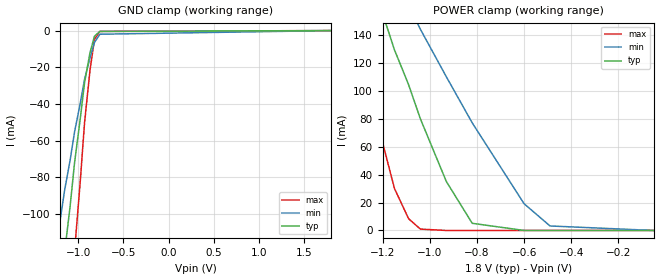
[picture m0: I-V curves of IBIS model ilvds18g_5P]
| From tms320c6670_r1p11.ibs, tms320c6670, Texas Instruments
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|   Model Cell ilvds18g_5P
|ilvds18g_5P
[Model]   ilvds18g_5P
Model_type   Input
Polarity   Non-Inverting
Vinl =  1.15
Vinh =  1.25
C_comp   0.840487p   0.785062p   0.905604p
[Model Spec]
Vinl   1.15   1.15   1.15
Vinh   1.25   1.25   1.25
[Temperature Range]   25   105   -40
[Voltage Range]   1.8   1.71   1.89
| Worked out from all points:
|   GND clamp passes 1 mA (typ) near -0.77 V on its own axis
|   POWER clamp passes 1 mA (typ) near -0.76 V on its own axis
[GND_clamp]
|   voltage   I(typ)   I(min)   I(max)
-1.8V     -438.9mA   -295.8mA   -676.9mA
-1.25V    -172mA     -120.3mA   -273.9mA
-1.2V     -146.2mA   -103.5mA   -234.6mA
-1.15V    -120.8mA   -86.95mA   -195.8mA
-1.09V    -95.96mA   -70.79mA   -157.5mA
-1.04V    -71.89mA   -55.15mA   -120mA
-980mV    -49.09mA   -40.28mA   -83.91mA
-930mV    -28.48mA   -26.62mA   -50.27mA
-870mV    -12.11mA   -14.93mA   -21.77mA
-820mV    -3.023mA   -6.438mA   -4.634mA
-760mV    -470.2uA   -1.993mA   -441.6uA
1.8V      23.4pA     3.455nA    19.89pA
[POWER_clamp]
|   voltage   I(typ)   I(min)   I(max)
-1.8V     448.2mA    392.9mA    487.2mA
-1.64V    367.1mA    338.8mA    366.4mA
-1.31V    207mA      231.6mA    132.1mA
-1.25V    180.9mA    213.9mA    95.42mA
-1.15V    129.4mA    178.8mA    30.1mA
-1.09V    104.4mA    161.4mA    8.438mA
-1.04V    79.98mA    144.1mA    975.6uA
-930mV    35.12mA    110.1mA    5.229uA
-820mV    5.137mA    77.05mA    25.89nA
-600mV    1.898uA    19.14mA    36.12pA
-490mV    29.59nA    3.23mA     32.66pA
-50mV     24.82pA    16.42nA    21.31pA
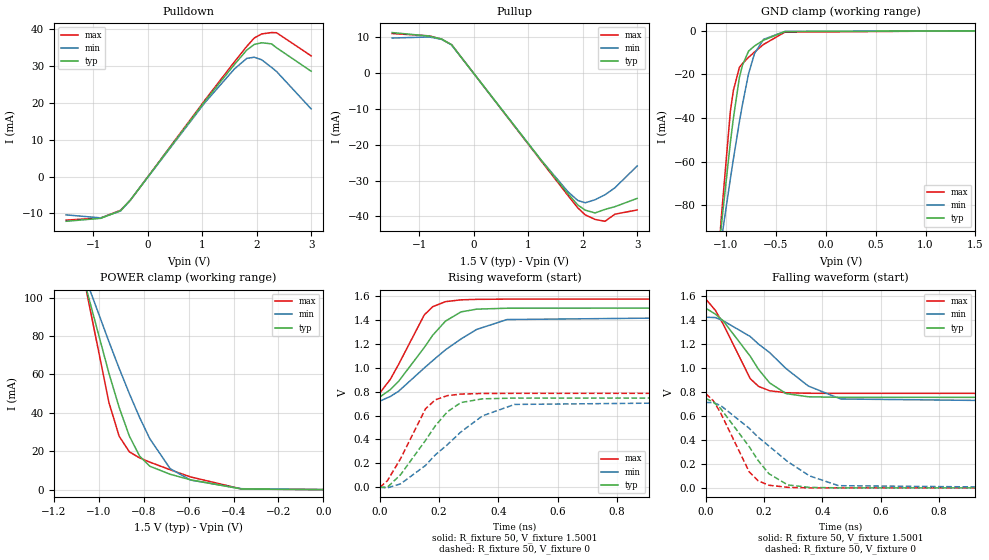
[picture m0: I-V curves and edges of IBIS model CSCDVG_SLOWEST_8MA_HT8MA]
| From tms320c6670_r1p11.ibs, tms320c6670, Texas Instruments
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|   Model Cell CSCDVG_SLOWEST_8MA_HT8MA
|SLOWEST_8MA
[Model]   CSCDVG_SLOWEST_8MA_HT8MA
Model_type   I/O
Polarity   Non-Inverting
Enable   Active-Low
Cref =  4.0000pF
Rref =  100.0000M
Vref =  0V
Vmeas =  0.75
C_comp   1.5249p   1.4275p   1.6205p
|[mode_tieoffpin] SR0=1  SR1=1 I0=0 I1=0 I2=1
[Model Spec]
Vinl   0.6125   0.6125   0.6125
Vinh   0.9625   0.9625   0.9625
D_overshoot_high 1.95 1.95 1.95
D_overshoot_low -0.3 -0.3 -0.3
D_overshoot_time 1E-9 1E-9 1E-9
S_overshoot_high 1.575 1.575 1.575
S_overshoot_low 0 0 0
[Receiver Thresholds]
Reference_supply Pullup_ref
Threshold_sensitivity= 0.5
Tslew_ac= 5nS
Vinh_ac= +175mV
Vinh_dc= +100mV
Vinl_ac= -175mV
Vinl_dc= -100mV
Vth = 0.75
Vth_max= 0.79
Vth_min= 0.71
[Pullup Reference] 1.5001   1.425   1.575
[Add Submodel]
|Submodel_name Mode
CSCDVG_HT_TH_8MA Non-Driving
[Temperature Range]   25   105   -40
[Voltage Range]   1.5   1.425   1.575
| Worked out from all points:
|   slope of the pulldown table from 0 to 0.225 V, typ, clamps not added: 50.1 ohm
|   slope of the pullup table from 0 to 0.225 V, typ, clamps not added: 50.1 ohm
|   GND clamp passes 1 mA (typ) near -0.47 V on its own axis
|   POWER clamp passes 1 mA (typ) near -0.42 V on its own axis
|   rising waveform, R_fixture 50, V_fixture 1.5001: 20-80 % time 136ps typ, 208ps min, 98ps max; typ from 0.756 V to 1.5 V
|   rising waveform, R_fixture 50, V_fixture 0: 20-80 % time 132ps typ, 191ps min, 95.4ps max; typ from 0 V to 0.747 V
|   falling waveform, R_fixture 50, V_fixture 1.5001: 20-80 % time 135ps typ, 202ps min, 94.9ps max; typ from 1.5 V to 0.755 V
|   falling waveform, R_fixture 50, V_fixture 0: 20-80 % time 132ps typ, 207ps min, 92.7ps max; typ from 0.746 V to 0 V
[POWER_clamp]
|   voltage   I(typ)   I(min)   I(max)
-1.5V     321.7mA    260.6mA    415.9mA
-1.076V   114.2mA    115.8mA    116.9mA
-1.061V   107.2mA    110.9mA    107.1mA
-954.6mV  60.59mA    77.06mA    45.35mA
-909.2mV  42.85mA    63.21mA    27.81mA
-863.7mV  27.9mA     49.99mA    19.69mA
-818.2mV  17.49mA    37.63mA    16.52mA
-772.8mV  12.19mA    26.53mA    14.33mA
-681.9mV  7.985mA    10.89mA    10.33mA
-590.9mV  5.094mA    4.955mA    6.6mA
-363.7mV  298.5uA    465.2uA    297.6uA
0V        1.518nA    24.08nA    367.8pA
[Pulldown]
|   voltage   I(typ)   I(min)   I(max)
-1.5V     -12.15mA   -10.4mA    -11.83mA
-863.7mV  -11.34mA   -11.22mA   -11.25mA
-500mV    -9.267mA   -9.352mA   -9.148mA
-318.2mV  -6.354mA   -6.371mA   -6.385mA
1.046V    20.42mA    20.05mA    20.72mA
1.591V    30.47mA    29.26mA    31.18mA
1.818V    34.39mA    32.13mA    35.4mA
1.955V    35.92mA    32.45mA    37.67mA
2.091V    36.38mA    31.76mA    38.77mA
2.273V    36.08mA    29.69mA    39.15mA
2.364V    35.03mA    28.59mA    39.11mA
3V        28.64mA    18.41mA    32.82mA
[Pullup]
|   voltage   I(typ)   I(min)   I(max)
-1.5V     11.21mA    9.69mA     10.94mA
-818.2mV  10.23mA    9.978mA    10.29mA
-590.9mV  9.401mA    9.328mA    9.374mA
-409.1mV  7.828mA    7.781mA    7.859mA
1.227V    -24.14mA   -24.11mA   -24.35mA
1.727V    -33.63mA   -33.09mA   -34.13mA
1.909V    -36.81mA   -35.55mA   -37.6mA
2.046V    -38.25mA   -36.2mA    -39.57mA
2.227V    -39.04mA   -35.36mA   -40.83mA
2.409V    -38.05mA   -33.98mA   -41.36mA
2.591V    -37.29mA   -32.03mA   -39.38mA
3V        -34.98mA   -25.95mA   -38.2mA
[GND_clamp]
|   voltage   I(typ)   I(min)   I(max)
-1.5V     -310.1mA   -250.5mA   -402.5mA
-1.076V   -103.6mA   -106.2mA   -105.2mA
-1.046V   -89.81mA   -96.36mA   -86.02mA
-954.6mV  -51.22mA   -67.87mA   -36.88mA
-924.3mV  -40.08mA   -58.86mA   -27.29mA
-863.7mV  -21.24mA   -41.56mA   -16.73mA
-833.4mV  -15.8mA    -33.75mA   -15.03mA
-772.8mV  -9.345mA   -19.75mA   -12.19mA
-712.2mV  -6.928mA   -10.35mA   -9.704mA
-621.3mV  -4.261mA   -3.896mA   -6.225mA
-409.1mV  -337.1uA   -289.1uA   -618.9uA
1.5V      1.518nA    257.2nA    299pA
[Ramp]
| variable   typ   min   max
dV/dt_f   0.596016/0.19469535n   0.56432/0.3101823n   0.629272/0.14102085n
dV/dt_r  0.6013584/0.19239092n 0.57508648/0.29752883n 0.63081544/0.1406002n
R_load = 50
[Rising Waveform]
R_fixture = 50
V_fixture = 1.5001
V_fixture_min = 1.425
V_fixture_max = 1.575
|   time   V(typ)   V(min)   V(max)
0s        755.9mV    721.6mV    789.3mV
35.49ps   817.7mV    760.2mV    904.4mV
62.87ps   885.6mV    803mV      1.027V
149.8ps   1.17V      998.8mV    1.443V
178.6ps   1.274V     1.061V     1.512V
221.3ps   1.391V     1.151V     1.554V
273.4ps   1.468V     1.241V     1.569V
326.2ps   1.491V     1.321V     1.573V
428.6ps   1.499V     1.404V     1.575V
1.283ns   1.5V       1.425V     1.575V
[Rising Waveform]
R_fixture = 50
V_fixture = 0
V_fixture_min = 0
V_fixture_max = 0
|   time   V(typ)   V(min)   V(max)
0s        0V         0V         0V
25.42ps   0V         -5.021mV   54.37mV
69.9ps    105.4mV    28.32mV    239.7mV
153.8ps   392.2mV    182.2mV    656.3mV
186.7ps   513.3mV    270.6mV    731.7mV
227.1ps   630.7mV    355.1mV    766.8mV
273.1ps   709mV      462.7mV    780.1mV
345.9ps   740.4mV    597.8mV    785.2mV
454.4ps   746.6mV    693.4mV    786.1mV
1.291ns   747.3mV    712.8mV    786.3mV
[Falling Waveform]
R_fixture = 50
V_fixture = 1.5001
V_fixture_min = 1.425
V_fixture_max = 1.575
|   time   V(typ)   V(min)   V(max)
0s        1.499V     1.424V     1.575V
33.01ps   1.449V     1.421V     1.48V
59.02ps   1.395V     1.395V     1.368V
152.3ps   1.098V     1.263V     910.9mV
180.5ps   989.3mV    1.2V       847.3mV
218.6ps   876.3mV    1.129V     810.4mV
275.3ps   786.6mV    995.1mV    793.7mV
351.6ps   760.1mV    849.6mV    789.3mV
462.4ps   755.6mV    741.7mV    788.7mV
1.283ns   755.2mV    720.6mV    788.5mV
[Falling Waveform]
R_fixture = 50
V_fixture = 0
V_fixture_min = 0
V_fixture_max = 0
|   time   V(typ)   V(min)   V(max)
0s        746.3mV    712.1mV    785.4mV
25.7ps    715.6mV    711.7mV    726.6mV
50.56ps   662.3mV    687.6mV    625.4mV
148.6ps   344mV      497.2mV    133.8mV
179.2ps   228.6mV    423.6mV    59.31mV
216.4ps   117.8mV    348.9mV    21.84mV
281.3ps   24.07mV    217.9mV    4.324mV
356ps     4.058mV    99.56mV    0V
455.4ps   0V         18.18mV    0V
1.291ns   0V         0V         0V
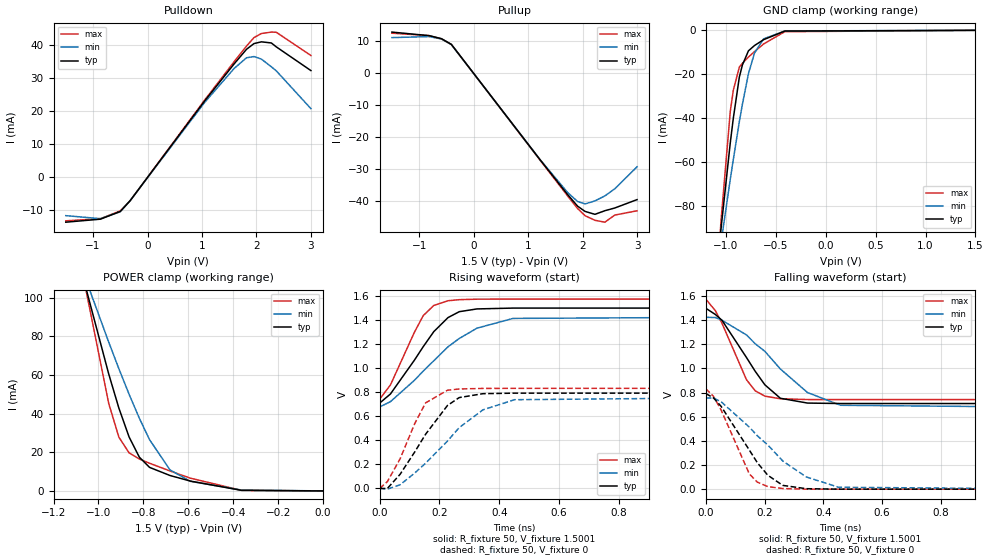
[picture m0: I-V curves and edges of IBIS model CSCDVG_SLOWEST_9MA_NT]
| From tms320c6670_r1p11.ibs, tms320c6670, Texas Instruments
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|   Model Cell CSCDVG_SLOWEST_9MA_NT
|SLOWEST_9MA
[Model]   CSCDVG_SLOWEST_9MA_NT
Model_type   I/O
Polarity   Non-Inverting
Enable   Active-Low
Cref =  4.0000pF
Rref =  100.0000M
Vref =  0V
Vmeas =  0.75
C_comp   1.5249p   1.4275p   1.6205p
|[mode_tieoffpin] SR0=1  SR1=1 I0=1 I1=0 I2=1
[Model Spec]
Vinl   0.6125   0.6125   0.6125
Vinh   0.9625   0.9625   0.9625
D_overshoot_high 1.95 1.95 1.95
D_overshoot_low -0.3 -0.3 -0.3
D_overshoot_time 1E-9 1E-9 1E-9
S_overshoot_high 1.575 1.575 1.575
S_overshoot_low 0 0 0
[Receiver Thresholds]
Reference_supply Pullup_ref
Threshold_sensitivity= 0.5
Tslew_ac= 5nS
Vinh_ac= +175mV
Vinh_dc= +100mV
Vinl_ac= -175mV
Vinl_dc= -100mV
Vth = 0.75
Vth_max= 0.79
Vth_min= 0.71
[Pullup Reference] 1.5001   1.425   1.575
[Add Submodel]
|Submodel_name Mode
CSCDVG_NT Non-Driving
[Temperature Range]   25   105   -40
[Voltage Range]   1.5   1.425   1.575
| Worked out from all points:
|   slope of the pulldown table from 0 to 0.225 V, typ, clamps not added: 44.4 ohm
|   slope of the pullup table from 0 to 0.225 V, typ, clamps not added: 44.4 ohm
|   GND clamp passes 1 mA (typ) near -0.47 V on its own axis
|   POWER clamp passes 1 mA (typ) near -0.42 V on its own axis
|   rising waveform, R_fixture 50, V_fixture 1.5001: 20-80 % time 133ps typ, 197ps min, 93.2ps max; typ from 0.71 V to 1.5 V
|   rising waveform, R_fixture 50, V_fixture 0: 20-80 % time 126ps typ, 187ps min, 90.7ps max; typ from 0 V to 0.793 V
|   falling waveform, R_fixture 50, V_fixture 1.5001: 20-80 % time 128ps typ, 194ps min, 90.3ps max; typ from 1.5 V to 0.709 V
|   falling waveform, R_fixture 50, V_fixture 0: 20-80 % time 128ps typ, 198ps min, 88.4ps max; typ from 0.793 V to 0 V
[POWER_clamp]
|   voltage   I(typ)   I(min)   I(max)
-1.5V     321.7mA    260.6mA    415.9mA
-1.076V   114.2mA    115.8mA    116.9mA
-1.061V   107.2mA    110.9mA    107.1mA
-954.6mV  60.59mA    77.06mA    45.35mA
-909.2mV  42.85mA    63.21mA    27.81mA
-863.7mV  27.9mA     49.99mA    19.69mA
-818.2mV  17.49mA    37.63mA    16.52mA
-772.8mV  12.19mA    26.53mA    14.33mA
-681.9mV  7.985mA    10.89mA    10.33mA
-590.9mV  5.094mA    4.955mA    6.6mA
-363.7mV  298.5uA    465.2uA    297.6uA
0V        1.518nA    24.08nA    367.8pA
[Pulldown]
|   voltage   I(typ)   I(min)   I(max)
-1.5V     -13.72mA   -11.73mA   -13.31mA
-863.7mV  -12.8mA    -12.65mA   -12.66mA
-500mV    -10.46mA   -10.55mA   -10.29mA
-318.2mV  -7.172mA   -7.186mA   -7.182mA
1.046V    23.05mA    22.61mA    23.31mA
1.591V    34.39mA    33mA       35.06mA
1.818V    38.82mA    36.24mA    39.81mA
1.955V    40.55mA    36.61mA    42.37mA
2.091V    41.08mA    35.83mA    43.61mA
2.273V    40.74mA    33.5mA     44.04mA
2.364V    39.55mA    32.26mA    43.99mA
3V        32.34mA    20.77mA    36.92mA
[Pullup]
|   voltage   I(typ)   I(min)   I(max)
-1.5V     12.66mA    10.94mA    12.31mA
-818.2mV  11.55mA    11.26mA    11.58mA
-590.9mV  10.61mA    10.52mA    10.54mA
-409.1mV  8.836mA    8.777mA    8.84mA
1.227V    -27.25mA   -27.19mA   -27.38mA
1.727V    -37.96mA   -37.32mA   -38.38mA
1.909V    -41.55mA   -40.1mA    -42.29mA
2.046V    -43.18mA   -40.84mA   -44.51mA
2.227V    -44.08mA   -39.9mA    -45.94mA
2.409V    -42.96mA   -38.35mA   -46.53mA
2.591V    -42.11mA   -36.14mA   -44.31mA
3V        -39.5mA    -29.28mA   -42.98mA
[GND_clamp]
|   voltage   I(typ)   I(min)   I(max)
-1.5V     -310.1mA   -250.5mA   -402.5mA
-1.076V   -103.6mA   -106.2mA   -105.2mA
-1.046V   -89.81mA   -96.36mA   -86.02mA
-954.6mV  -51.22mA   -67.87mA   -36.88mA
-924.3mV  -40.08mA   -58.86mA   -27.29mA
-863.7mV  -21.24mA   -41.56mA   -16.73mA
-833.4mV  -15.8mA    -33.75mA   -15.03mA
-772.8mV  -9.345mA   -19.75mA   -12.19mA
-712.2mV  -6.928mA   -10.35mA   -9.704mA
-621.3mV  -4.261mA   -3.896mA   -6.225mA
-409.1mV  -337.1uA   -289.1uA   -618.9uA
1.5V      1.518nA    257.2nA    299pA
[Ramp]
| variable   typ   min   max
dV/dt_f   0.632912/0.18543928n   0.59944/0.30124073n   0.666584/0.13417172n
dV/dt_r 0.63885392/0.18548444n 0.61071216/0.28637454n 0.66808936/0.13313997n
R_load = 50
[Rising Waveform]
R_fixture = 50
V_fixture = 1.5001
V_fixture_min = 1.425
V_fixture_max = 1.575
|   time   V(typ)   V(min)   V(max)
0s        709.9mV    677.9mV    742.7mV
35.96ps   785.4mV    721.7mV    860.4mV
115.9ps   1.066V     898.8mV    1.298V
145.6ps   1.179V     975.8mV    1.437V
180.9ps   1.304V     1.062V     1.522V
228.5ps   1.421V     1.178V     1.561V
266ps     1.47V      1.247V     1.57V
325.2ps   1.493V     1.333V     1.574V
445.9ps   1.5V       1.414V     1.575V
1.282ns   1.5V       1.425V     1.575V
[Rising Waveform]
R_fixture = 50
V_fixture = 0
V_fixture_min = 0
V_fixture_max = 0
|   time   V(typ)   V(min)   V(max)
0s        0V         0V         0V
25.81ps   0V         -5.884mV   56.92mV
68.17ps   117.3mV    30.35mV    245.7mV
116.7ps   301.5mV    127.2mV    536.8mV
153.6ps   451.1mV    210.1mV    711.8mV
226.6ps   689.9mV    394.2mV    816.8mV
265.7ps   755.6mV    505.6mV    827.2mV
345ps     788.1mV    653.4mV    831.9mV
450.6ps   792.5mV    738.1mV    832.6mV
1.29ns    793mV      756.2mV    832.8mV
[Falling Waveform]
R_fixture = 50
V_fixture = 1.5001
V_fixture_min = 1.425
V_fixture_max = 1.575
|   time   V(typ)   V(min)   V(max)
0s        1.499V     1.424V     1.575V
32.81ps   1.447V     1.422V     1.478V
55.23ps   1.399V     1.399V     1.374V
138.4ps   1.091V     1.278V     907.3mV
168.2ps   976.6mV    1.205V     814.6mV
201.1ps   864.5mV    1.142V     770.7mV
253.9ps   753mV      995.5mV    748.6mV
346.2ps   713.3mV    800.4mV    742.6mV
458.8ps   709.6mV    695mV      742mV
1.282ns   709.3mV    676.9mV    741.9mV
[Falling Waveform]
R_fixture = 50
V_fixture = 0
V_fixture_min = 0
V_fixture_max = 0
|   time   V(typ)   V(min)   V(max)
0s        792.6mV    755.6mV    831.9mV
26.46ps   755.7mV    754.5mV    768.3mV
52.33ps   685.8mV    724.3mV    654.9mV
148.1ps   324.5mV    514.2mV    126.7mV
175.3ps   219.5mV    442.6mV    58.45mV
211.3ps   114.7mV    365.5mV    20.8mV
262.1ps   31.27mV    233.1mV    5.334mV
342ps     3.945mV    100.9mV    0V
452.3ps   0V         15.76mV    0V
1.29ns    0V         0V         0V
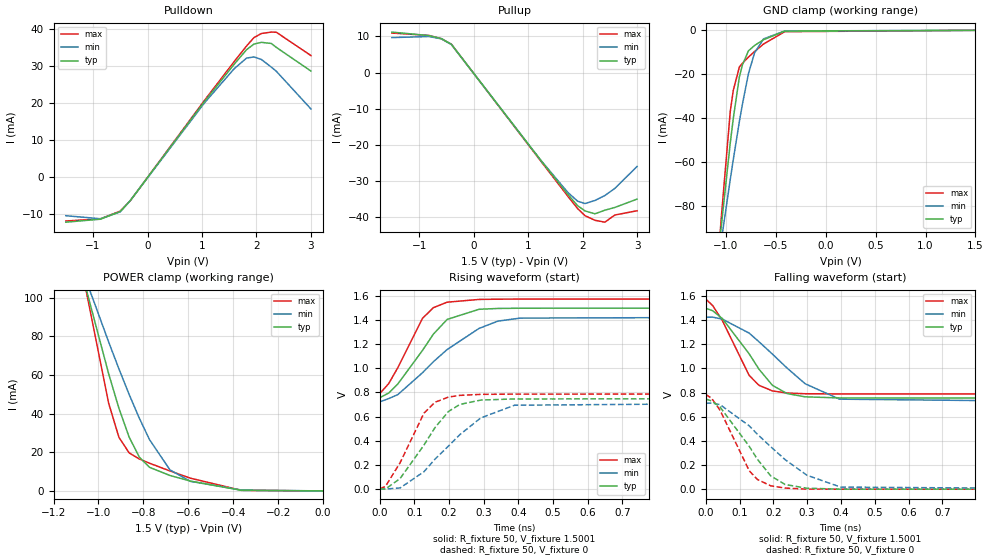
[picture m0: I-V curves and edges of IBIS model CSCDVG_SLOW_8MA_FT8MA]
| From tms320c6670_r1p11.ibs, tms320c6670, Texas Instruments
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|   Model Cell CSCDVG_SLOW_8MA_FT8MA
|SLOW_8MA
[Model]   CSCDVG_SLOW_8MA_FT8MA
Model_type   I/O
Polarity   Non-Inverting
Enable   Active-Low
Cref =  4.0000pF
Rref =  100.0000M
Vref =  0V
Vmeas =  0.75
C_comp   1.5249p   1.4275p   1.6205p
|[mode_tieoffpin] SR0=0  SR1=1 I0=0 I1=0 I2=1
[Model Spec]
Vinl   0.6125   0.6125   0.6125
Vinh   0.9625   0.9625   0.9625
D_overshoot_high 1.95 1.95 1.95
D_overshoot_low -0.3 -0.3 -0.3
D_overshoot_time 1E-9 1E-9 1E-9
S_overshoot_high 1.575 1.575 1.575
S_overshoot_low 0 0 0
[Receiver Thresholds]
Reference_supply Pullup_ref
Threshold_sensitivity= 0.5
Tslew_ac= 5nS
Vinh_ac= +175mV
Vinh_dc= +100mV
Vinl_ac= -175mV
Vinl_dc= -100mV
Vth = 0.75
Vth_max= 0.79
Vth_min= 0.71
[Pullup Reference] 1.5001   1.425   1.575
[Add Submodel]
|Submodel_name Mode
CSCDVG_FT_TH_8MA Non-Driving
[Temperature Range]   25   105   -40
[Voltage Range]   1.5   1.425   1.575
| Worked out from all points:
|   slope of the pulldown table from 0 to 0.225 V, typ, clamps not added: 50.1 ohm
|   slope of the pullup table from 0 to 0.225 V, typ, clamps not added: 50.1 ohm
|   GND clamp passes 1 mA (typ) near -0.47 V on its own axis
|   POWER clamp passes 1 mA (typ) near -0.42 V on its own axis
|   rising waveform, R_fixture 50, V_fixture 1.5001: 20-80 % time 112ps typ, 168ps min, 83.3ps max; typ from 0.756 V to 1.5 V
|   rising waveform, R_fixture 50, V_fixture 0: 20-80 % time 108ps typ, 154ps min, 80.3ps max; typ from 0 V to 0.747 V
|   falling waveform, R_fixture 50, V_fixture 1.5001: 20-80 % time 114ps typ, 168ps min, 82.8ps max; typ from 1.5 V to 0.755 V
|   falling waveform, R_fixture 50, V_fixture 0: 20-80 % time 111ps typ, 172ps min, 80.3ps max; typ from 0.746 V to 0 V
[POWER_clamp]
|   voltage   I(typ)   I(min)   I(max)
-1.5V     321.7mA    260.6mA    415.9mA
-1.076V   114.2mA    115.8mA    116.9mA
-1.061V   107.2mA    110.9mA    107.1mA
-954.6mV  60.59mA    77.06mA    45.35mA
-909.2mV  42.85mA    63.21mA    27.81mA
-863.7mV  27.9mA     49.99mA    19.69mA
-818.2mV  17.49mA    37.63mA    16.52mA
-772.8mV  12.19mA    26.53mA    14.33mA
-681.9mV  7.985mA    10.89mA    10.33mA
-590.9mV  5.094mA    4.955mA    6.6mA
-363.7mV  298.5uA    465.2uA    297.6uA
0V        1.518nA    24.08nA    367.8pA
[Pulldown]
|   voltage   I(typ)   I(min)   I(max)
-1.5V     -12.15mA   -10.4mA    -11.83mA
-863.7mV  -11.34mA   -11.22mA   -11.25mA
-500mV    -9.267mA   -9.352mA   -9.148mA
-318.2mV  -6.354mA   -6.371mA   -6.385mA
1.046V    20.42mA    20.05mA    20.72mA
1.591V    30.47mA    29.26mA    31.18mA
1.818V    34.39mA    32.13mA    35.4mA
1.955V    35.92mA    32.45mA    37.67mA
2.091V    36.38mA    31.76mA    38.77mA
2.273V    36.08mA    29.69mA    39.15mA
2.364V    35.03mA    28.59mA    39.11mA
3V        28.64mA    18.41mA    32.82mA
[Pullup]
|   voltage   I(typ)   I(min)   I(max)
-1.5V     11.21mA    9.69mA     10.94mA
-818.2mV  10.23mA    9.978mA    10.29mA
-590.9mV  9.401mA    9.328mA    9.374mA
-409.1mV  7.828mA    7.781mA    7.859mA
1.227V    -24.14mA   -24.11mA   -24.35mA
1.727V    -33.63mA   -33.09mA   -34.13mA
1.909V    -36.81mA   -35.55mA   -37.6mA
2.046V    -38.25mA   -36.2mA    -39.57mA
2.227V    -39.04mA   -35.36mA   -40.83mA
2.409V    -38.05mA   -33.98mA   -41.36mA
2.591V    -37.29mA   -32.03mA   -39.38mA
3V        -34.98mA   -25.95mA   -38.2mA
[GND_clamp]
|   voltage   I(typ)   I(min)   I(max)
-1.5V     -310.1mA   -250.5mA   -402.5mA
-1.076V   -103.6mA   -106.2mA   -105.2mA
-1.046V   -89.81mA   -96.36mA   -86.02mA
-954.6mV  -51.22mA   -67.87mA   -36.88mA
-924.3mV  -40.08mA   -58.86mA   -27.29mA
-863.7mV  -21.24mA   -41.56mA   -16.73mA
-833.4mV  -15.8mA    -33.75mA   -15.03mA
-772.8mV  -9.345mA   -19.75mA   -12.19mA
-712.2mV  -6.928mA   -10.35mA   -9.704mA
-621.3mV  -4.261mA   -3.896mA   -6.225mA
-409.1mV  -337.1uA   -289.1uA   -618.9uA
1.5V      1.518nA    257.2nA    299pA
[Ramp]
| variable   typ   min   max
dV/dt_f   0.596016/0.16747067n   0.56408/0.25220681n   0.629272/0.12664996n
dV/dt_r 0.60150488/0.15902866n  0.5749704/0.2367164n  0.6310776/0.12226898n
R_load = 50
[Rising Waveform]
R_fixture = 50
V_fixture = 1.5001
V_fixture_min = 1.425
V_fixture_max = 1.575
|   time   V(typ)   V(min)   V(max)
0s        755.9mV    721.1mV    789.3mV
26.08ps   794.8mV    748.7mV    873mV
52.37ps   869.7mV    781.6mV    1.005V
123.7ps   1.149V     963.5mV    1.415V
154.8ps   1.283V     1.054V     1.503V
194.8ps   1.406V     1.156V     1.549V
286.6ps   1.49V      1.331V     1.572V
341.3ps   1.497V     1.392V     1.574V
405.7ps   1.499V     1.417V     1.575V
1.291ns   1.5V       1.425V     1.575V
[Rising Waveform]
R_fixture = 50
V_fixture = 0
V_fixture_min = 0
V_fixture_max = 0
|   time   V(typ)   V(min)   V(max)
0s        0V         0V         0V
16.45ps   -3.235mV   -2.5mV     18.64mV
58.93ps   85.17mV    6.841mV    215.7mV
127.9ps   362.9mV    141.9mV    628.2mV
160ps     509.3mV    246.9mV    718.7mV
198.5ps   641.5mV    354.1mV    761.4mV
231.4ps   700.1mV    449.2mV    775.4mV
291.7ps   736.3mV    588.2mV    783.7mV
389.1ps   746mV      693.6mV    785.9mV
1.298ns   747.3mV    712.8mV    786.3mV
[Falling Waveform]
R_fixture = 50
V_fixture = 1.5001
V_fixture_min = 1.425
V_fixture_max = 1.575
|   time   V(typ)   V(min)   V(max)
0s        1.499V     1.424V     1.575V
20.45ps   1.478V     1.425V     1.521V
48.81ps   1.414V     1.409V     1.398V
128.4ps   1.121V     1.293V     942.3mV
157.5ps   993.7mV    1.221V     860.6mV
197.2ps   860.3mV    1.119V     814.1mV
240.3ps   792.2mV    1.004V     796.4mV
294.3ps   764.9mV    873mV      790.6mV
395.9ps   756mV      745.7mV    788.8mV
1.291ns   755.2mV    720.6mV    788.5mV
[Falling Waveform]
R_fixture = 50
V_fixture = 0
V_fixture_min = 0
V_fixture_max = 0
|   time   V(typ)   V(min)   V(max)
0s        746.4mV    711.9mV    785.4mV
17.52ps   731.2mV    713.4mV    751.9mV
42.22ps   680.3mV    700.5mV    654.1mV
128.7ps   354.6mV    524.3mV    152.3mV
152.6ps   248.2mV    455.5mV    80.57mV
192.1ps   110.3mV    351.7mV    27.93mV
234.9ps   38.42mV    244.6mV    8.931mV
299.2ps   8.068mV    115.5mV    320.3uV
399ps     0V         17.19mV    0V
1.298ns   0V         0V         0V
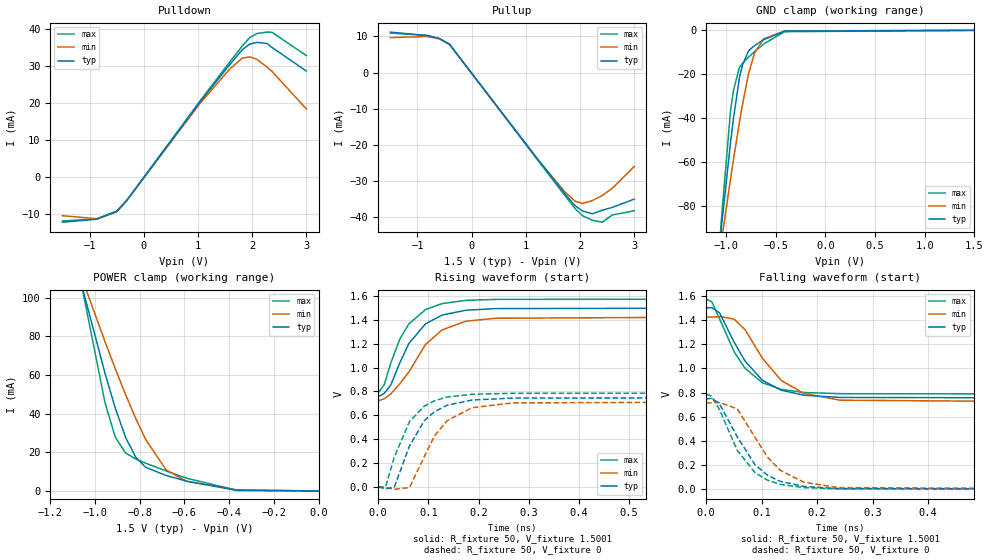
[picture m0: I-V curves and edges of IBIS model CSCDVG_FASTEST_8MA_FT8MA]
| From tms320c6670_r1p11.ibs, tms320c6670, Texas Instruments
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|   Model Cell CSCDVG_FASTEST_8MA_FT8MA
|FASTEST_8MA
[Model]   CSCDVG_FASTEST_8MA_FT8MA
Model_type   I/O
Polarity   Non-Inverting
Enable   Active-Low
Cref =  4.0000pF
Rref =  100.0000M
Vref =  0V
Vmeas =  0.75
C_comp   1.5249p   1.4275p   1.6205p
|[mode_tieoffpin] SR0=0  SR1=0 I0=0 I1=0 I2=1
[Model Spec]
Vinl   0.6125   0.6125   0.6125
Vinh   0.9625   0.9625   0.9625
D_overshoot_high 1.95 1.95 1.95
D_overshoot_low -0.3 -0.3 -0.3
D_overshoot_time 1E-9 1E-9 1E-9
S_overshoot_high 1.575 1.575 1.575
S_overshoot_low 0 0 0
[Receiver Thresholds]
Reference_supply Pullup_ref
Threshold_sensitivity= 0.5
Tslew_ac= 5nS
Vinh_ac= +175mV
Vinh_dc= +100mV
Vinl_ac= -175mV
Vinl_dc= -100mV
Vth = 0.75
Vth_max= 0.79
Vth_min= 0.71
[Pullup Reference] 1.5001   1.425   1.575
[Add Submodel]
|Submodel_name Mode
CSCDVG_FT_TH_8MA Non-Driving
[Temperature Range]   25   105   -40
[Voltage Range]   1.5   1.425   1.575
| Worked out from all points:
|   slope of the pulldown table from 0 to 0.225 V, typ, clamps not added: 50.1 ohm
|   slope of the pullup table from 0 to 0.225 V, typ, clamps not added: 50.1 ohm
|   GND clamp passes 1 mA (typ) near -0.47 V on its own axis
|   POWER clamp passes 1 mA (typ) near -0.42 V on its own axis
|   rising waveform, R_fixture 50, V_fixture 1.5001: 20-80 % time 58.3ps typ, 73.4ps min, 53.6ps max; typ from 0.756 V to 1.5 V
|   rising waveform, R_fixture 50, V_fixture 0: 20-80 % time 55.5ps typ, 60.1ps min, 51.7ps max; typ from 0 V to 0.747 V
|   falling waveform, R_fixture 50, V_fixture 1.5001: 20-80 % time 63.9ps typ, 71.2ps min, 58.3ps max; typ from 1.5 V to 0.755 V
|   falling waveform, R_fixture 50, V_fixture 0: 20-80 % time 61.7ps typ, 66.4ps min, 55.7ps max; typ from 0.747 V to 0 V
[POWER_clamp]
|   voltage   I(typ)   I(min)   I(max)
-1.5V     321.7mA    260.6mA    415.9mA
-1.076V   114.2mA    115.8mA    116.9mA
-1.061V   107.2mA    110.9mA    107.1mA
-954.6mV  60.59mA    77.06mA    45.35mA
-909.2mV  42.85mA    63.21mA    27.81mA
-863.7mV  27.9mA     49.99mA    19.69mA
-818.2mV  17.49mA    37.63mA    16.52mA
-772.8mV  12.19mA    26.53mA    14.33mA
-681.9mV  7.985mA    10.89mA    10.33mA
-590.9mV  5.094mA    4.955mA    6.6mA
-363.7mV  298.5uA    465.2uA    297.6uA
0V        1.518nA    24.08nA    367.8pA
[Pulldown]
|   voltage   I(typ)   I(min)   I(max)
-1.5V     -12.15mA   -10.4mA    -11.83mA
-863.7mV  -11.34mA   -11.22mA   -11.25mA
-500mV    -9.267mA   -9.352mA   -9.148mA
-318.2mV  -6.354mA   -6.371mA   -6.385mA
1.046V    20.42mA    20.05mA    20.72mA
1.591V    30.47mA    29.26mA    31.18mA
1.818V    34.39mA    32.13mA    35.4mA
1.955V    35.92mA    32.45mA    37.67mA
2.091V    36.38mA    31.76mA    38.77mA
2.273V    36.08mA    29.69mA    39.15mA
2.364V    35.03mA    28.59mA    39.11mA
3V        28.64mA    18.41mA    32.82mA
[Pullup]
|   voltage   I(typ)   I(min)   I(max)
-1.5V     11.21mA    9.69mA     10.94mA
-818.2mV  10.23mA    9.978mA    10.29mA
-590.9mV  9.401mA    9.328mA    9.374mA
-409.1mV  7.828mA    7.781mA    7.859mA
1.227V    -24.14mA   -24.11mA   -24.35mA
1.727V    -33.63mA   -33.09mA   -34.13mA
1.909V    -36.81mA   -35.55mA   -37.6mA
2.046V    -38.25mA   -36.2mA    -39.57mA
2.227V    -39.04mA   -35.36mA   -40.83mA
2.409V    -38.05mA   -33.98mA   -41.36mA
2.591V    -37.29mA   -32.03mA   -39.38mA
3V        -34.98mA   -25.95mA   -38.2mA
[GND_clamp]
|   voltage   I(typ)   I(min)   I(max)
-1.5V     -310.1mA   -250.5mA   -402.5mA
-1.076V   -103.6mA   -106.2mA   -105.2mA
-1.046V   -89.81mA   -96.36mA   -86.02mA
-954.6mV  -51.22mA   -67.87mA   -36.88mA
-924.3mV  -40.08mA   -58.86mA   -27.29mA
-863.7mV  -21.24mA   -41.56mA   -16.73mA
-833.4mV  -15.8mA    -33.75mA   -15.03mA
-772.8mV  -9.345mA   -19.75mA   -12.19mA
-712.2mV  -6.928mA   -10.35mA   -9.704mA
-621.3mV  -4.261mA   -3.896mA   -6.225mA
-409.1mV  -337.1uA   -289.1uA   -618.9uA
1.5V      1.518nA    257.2nA    299pA
[Ramp]
| variable   typ   min   max
dV/dt_f   0.600016/0.10061207n   0.567752/0.11362969n   0.630472/91.451266p
dV/dt_r  0.6179528/90.31641p   0.5951272/98.680182p  0.6425552/82.389602p
R_load = 50
[Rising Waveform]
R_fixture = 50
V_fixture = 1.5001
V_fixture_min = 1.425
V_fixture_max = 1.575
|   time   V(typ)   V(min)   V(max)
0s        755.9mV    721.1mV    789.3mV
11.97ps   783.8mV    739.3mV    856.4mV
24.97ps   852.9mV    779.7mV    1.037V
43.07ps   1.04V      864mV      1.24V
61.17ps   1.203V     964mV      1.367V
94.28ps   1.367V     1.194V     1.487V
127.2ps   1.441V     1.316V     1.537V
174.3ps   1.481V     1.389V     1.564V
232.9ps   1.495V     1.414V     1.572V
747.8ps   1.5V       1.425V     1.575V
[Rising Waveform]
R_fixture = 50
V_fixture = 0
V_fixture_min = 0
V_fixture_max = 0
|   time   V(typ)   V(min)   V(max)
0s        0V         0V         0V
14.58ps   -16.66mV   -6.84mV    0V
32.29ps   0V         -18.98mV   252.1mV
62.35ps   343.4mV    -5.595mV   548.1mV
91.92ps   555.5mV    254.6mV    677.3mV
112ps     629.5mV    426.2mV    721.9mV
137.4ps   685.3mV    555.1mV    753.9mV
187.1ps   728.4mV    663.7mV    776.9mV
267.3ps   744.4mV    704.2mV    784.8mV
820.8ps   747.3mV    712.8mV    786.3mV
[Falling Waveform]
R_fixture = 50
V_fixture = 1.5001
V_fixture_min = 1.425
V_fixture_max = 1.575
|   time   V(typ)   V(min)   V(max)
0s        1.501V     1.426V     1.575V
10.31ps   1.504V     1.426V     1.552V
24.3ps    1.461V     1.43V      1.41V
50.37ps   1.219V     1.409V     1.14V
70.21ps   1.061V     1.321V     1.001V
101.5ps   901.9mV    1.085V     882.1mV
135.5ps   819.7mV    900.2mV    826.4mV
177ps     778mV      791.9mV    800.8mV
241.8ps   759.9mV    737mV      790.9mV
747.8ps   755.2mV    720.6mV    788.5mV
[Falling Waveform]
R_fixture = 50
V_fixture = 0
V_fixture_min = 0
V_fixture_max = 0
|   time   V(typ)   V(min)   V(max)
0s        747.4mV    713.5mV    785.8mV
8.957ps   752.2mV    715.2mV    772.9mV
23.12ps   715.1mV    718.5mV    669mV
56ps      434.4mV    667.4mV    322.8mV
88.45ps   200.9mV    427.3mV    134.8mV
110.5ps   116.1mV    266.6mV    74.99mV
133.4ps   64.8mV     157.2mV    39.69mV
176.2ps   22.85mV    57.28mV    12.69mV
238ps     4.788mV    13.15mV    2.719mV
820.8ps   0V         0V         0V
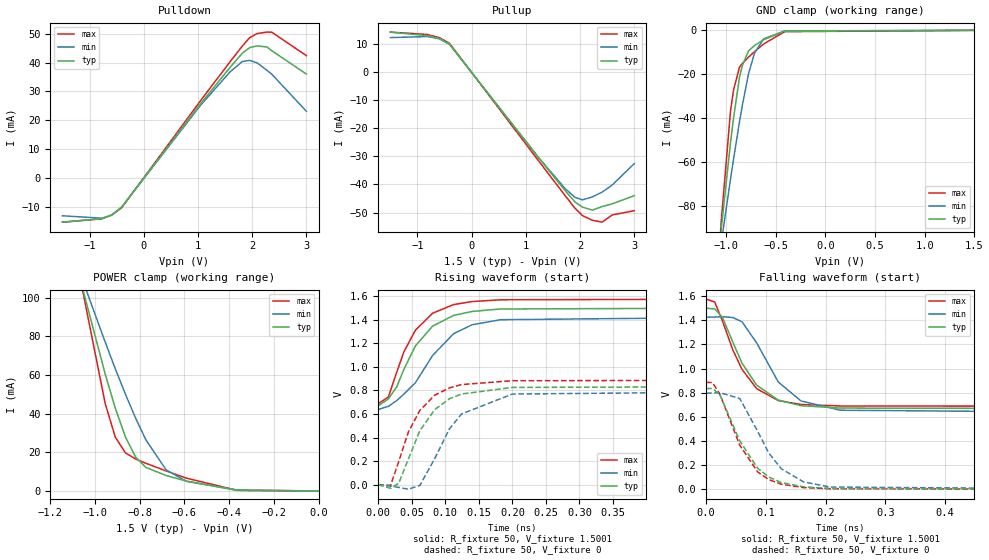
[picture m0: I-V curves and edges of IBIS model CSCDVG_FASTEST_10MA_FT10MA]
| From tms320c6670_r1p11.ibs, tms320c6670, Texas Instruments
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|   Model Cell CSCDVG_FASTEST_10MA_FT10MA
|FASTEST_10MA
[Model]   CSCDVG_FASTEST_10MA_FT10MA
Model_type   I/O
Polarity   Non-Inverting
Enable   Active-Low
Cref =  4.0000pF
Rref =  100.0000M
Vref =  0V
Vmeas =  0.75
C_comp   1.5249p   1.4275p   1.6205p
|[mode_tieoffpin] SR0=0  SR1=0 I0=0 I1=1 I2=1
[Model Spec]
Vinl   0.6125   0.6125   0.6125
Vinh   0.9625   0.9625   0.9625
D_overshoot_high 1.95 1.95 1.95
D_overshoot_low -0.3 -0.3 -0.3
D_overshoot_time 1E-9 1E-9 1E-9
S_overshoot_high 1.575 1.575 1.575
S_overshoot_low 0 0 0
[Receiver Thresholds]
Reference_supply Pullup_ref
Threshold_sensitivity= 0.5
Tslew_ac= 5nS
Vinh_ac= +175mV
Vinh_dc= +100mV
Vinl_ac= -175mV
Vinl_dc= -100mV
Vth = 0.75
Vth_max= 0.79
Vth_min= 0.71
[Pullup Reference] 1.5001   1.425   1.575
[Add Submodel]
|Submodel_name Mode
CSCDVG_FT_TH_10MA Non-Driving
[Temperature Range]   25   105   -40
[Voltage Range]   1.5   1.425   1.575
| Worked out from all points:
|   slope of the pulldown table from 0 to 0.225 V, typ, clamps not added: 39.9 ohm
|   slope of the pullup table from 0 to 0.225 V, typ, clamps not added: 39.8 ohm
|   GND clamp passes 1 mA (typ) near -0.47 V on its own axis
|   POWER clamp passes 1 mA (typ) near -0.42 V on its own axis
|   rising waveform, R_fixture 50, V_fixture 1.5001: 20-80 % time 50.6ps typ, 66ps min, 45.5ps max; typ from 0.669 V to 1.5 V
|   rising waveform, R_fixture 50, V_fixture 0: 20-80 % time 48.3ps typ, 52ps min, 44.1ps max; typ from 0 V to 0.834 V
|   falling waveform, R_fixture 50, V_fixture 1.5001: 20-80 % time 54.5ps typ, 60.1ps min, 51.1ps max; typ from 1.5 V to 0.669 V
|   falling waveform, R_fixture 50, V_fixture 0: 20-80 % time 53ps typ, 56.3ps min, 49.6ps max; typ from 0.834 V to 0 V
[POWER_clamp]
|   voltage   I(typ)   I(min)   I(max)
-1.5V     321.7mA    260.6mA    415.9mA
-1.076V   114.2mA    115.8mA    116.9mA
-1.061V   107.2mA    110.9mA    107.1mA
-954.6mV  60.59mA    77.06mA    45.35mA
-909.2mV  42.85mA    63.21mA    27.81mA
-863.7mV  27.9mA     49.99mA    19.69mA
-818.2mV  17.49mA    37.63mA    16.52mA
-772.8mV  12.19mA    26.53mA    14.33mA
-681.9mV  7.985mA    10.89mA    10.33mA
-590.9mV  5.094mA    4.955mA    6.6mA
-363.7mV  298.5uA    465.2uA    297.6uA
0V        1.518nA    24.08nA    367.8pA
[Pulldown]
|   voltage   I(typ)   I(min)   I(max)
-1.5V     -15.29mA   -13.07mA   -15.28mA
-772.8mV  -14.07mA   -13.9mA    -14.11mA
-590.9mV  -12.74mA   -12.86mA   -12.82mA
-409.1mV  -10.08mA   -10.11mA   -10.32mA
1.046V    25.68mA    25.17mA    26.75mA
1.591V    38.31mA    36.75mA    40.25mA
1.818V    43.24mA    40.36mA    45.69mA
1.955V    45.18mA    40.77mA    48.64mA
2.091V    45.77mA    39.91mA    50.06mA
2.273V    45.4mA     37.32mA    50.56mA
2.364V    44.07mA    35.93mA    50.51mA
3V        36.04mA    23.14mA    42.4mA
[Pullup]
|   voltage   I(typ)   I(min)   I(max)
-1.5V     14.1mA     12.18mA    14.13mA
-818.2mV  12.87mA    12.54mA    13.29mA
-590.9mV  11.83mA    11.72mA    12.11mA
-409.1mV  9.844mA    9.773mA    10.15mA
1.227V    -30.36mA   -30.27mA   -31.43mA
1.727V    -42.29mA   -41.55mA   -44.05mA
1.909V    -46.29mA   -44.65mA   -48.54mA
2.046V    -48.11mA   -45.48mA   -51.1mA
2.227V    -49.12mA   -44.44mA   -52.74mA
2.409V    -47.87mA   -42.71mA   -53.43mA
2.591V    -46.92mA   -40.26mA   -50.87mA
3V        -44.02mA   -32.61mA   -49.35mA
[GND_clamp]
|   voltage   I(typ)   I(min)   I(max)
-1.5V     -310.1mA   -250.5mA   -402.5mA
-1.076V   -103.6mA   -106.2mA   -105.2mA
-1.046V   -89.81mA   -96.36mA   -86.02mA
-954.6mV  -51.22mA   -67.87mA   -36.88mA
-924.3mV  -40.08mA   -58.86mA   -27.29mA
-863.7mV  -21.24mA   -41.56mA   -16.73mA
-833.4mV  -15.8mA    -33.75mA   -15.03mA
-772.8mV  -9.345mA   -19.75mA   -12.19mA
-712.2mV  -6.928mA   -10.35mA   -9.704mA
-621.3mV  -4.261mA   -3.896mA   -6.225mA
-409.1mV  -337.1uA   -289.1uA   -618.9uA
1.5V      1.518nA    257.2nA    299pA
[Ramp]
| variable   typ   min   max
dV/dt_f   0.669864/87.003099p   0.633872/97.606683p   0.71256/79.867155p
dV/dt_r   0.69126/78.484022p   0.666572/85.514205p  0.7275984/70.847508p
R_load = 50
[Rising Waveform]
R_fixture = 50
V_fixture = 1.5001
V_fixture_min = 1.425
V_fixture_max = 1.575
|   time   V(typ)   V(min)   V(max)
0s        669.2mV    638.7mV    688.3mV
15.12ps   727.9mV    664.7mV    743.7mV
27.67ps   830.8mV    714mV      955.2mV
38.44ps   981mV      769.7mV    1.129V
55.49ps   1.178V     865.9mV    1.311V
81.19ps   1.346V     1.097V     1.455V
112.3ps   1.436V     1.281V     1.528V
139.8ps   1.47V      1.357V     1.554V
182.6ps   1.491V     1.4V       1.569V
633.2ps   1.5V       1.425V     1.575V
[Rising Waveform]
R_fixture = 50
V_fixture = 0
V_fixture_min = 0
V_fixture_max = 0
|   time   V(typ)   V(min)   V(max)
0s        0V         0V         0V
18.54ps   -30.56mV   -11.4mV    -4.729mV
30.59ps   12.86mV    -22.26mV   197.4mV
44.84ps   216.6mV    -37.22mV   445.9mV
62.05ps   458.5mV    -6.175mV   630.8mV
84.26ps   637.7mV    222.4mV    759.9mV
106.1ps   729mV      474mV      821.5mV
124.3ps   769.7mV    600.6mV    849.8mV
199.9ps   825.6mV    769.6mV    882.7mV
704.5ps   833.5mV    794.6mV    886.9mV
[Falling Waveform]
R_fixture = 50
V_fixture = 1.5001
V_fixture_min = 1.425
V_fixture_max = 1.575
|   time   V(typ)   V(min)   V(max)
0s        1.5V       1.426V     1.576V
14.44ps   1.494V     1.427V     1.552V
27.28ps   1.425V     1.43V      1.395V
44.67ps   1.219V     1.423V     1.155V
59.99ps   1.045V     1.388V     993.6mV
84.53ps   862.7mV    1.213V     833.3mV
120.7ps   738.1mV    888.5mV    734.9mV
158.8ps   692.2mV    731.2mV    701.8mV
224.4ps   672.2mV    654.5mV    689.9mV
633.2ps   668.6mV    638.2mV    687.6mV
[Falling Waveform]
R_fixture = 50
V_fixture = 0
V_fixture_min = 0
V_fixture_max = 0
|   time   V(typ)   V(min)   V(max)
0s        833.8mV    795.3mV    885.9mV
10.74ps   834.8mV    797.3mV    883.2mV
23.03ps   783.2mV    799.9mV    786.4mV
56.25ps   400.4mV    752.1mV    364.9mV
86.26ps   173mV      479.7mV    142.2mV
104.9ps   100.8mV    299.3mV    79.49mV
125.7ps   55mV       169.6mV    41.31mV
163ps     18.86mV    60.23mV    13.11mV
207.5ps   5.721mV    17.7mV     3.516mV
704.5ps   0V         0V         0V
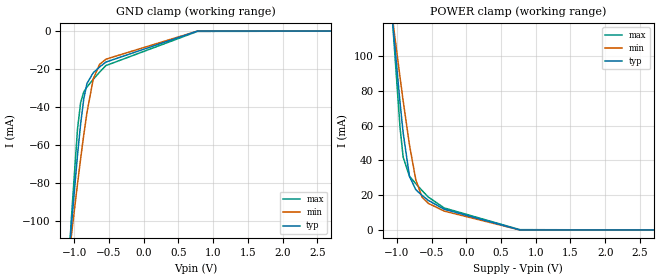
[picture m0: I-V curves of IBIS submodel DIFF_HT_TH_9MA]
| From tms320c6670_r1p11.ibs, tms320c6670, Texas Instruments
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|   Model Cell DIFF_HT_TH_9MA
|DIFF_HT_TH_9MA
[Submodel]   DIFF_HT_TH_9MA
Submodel_type   Dynamic_clamp
[POWER_clamp]
|   voltage   I(typ)   I(min)   I(max)
-1.5V     333.3mA    269mA      428.4mA
-1.091V   133.8mA    131.1mA    140.1mA
-1.046V   113mA      116.4mA    110.8mA
-954.6mV  73.51mA    87.92mA    59.15mA
-909.2mV  55.86mA    74.22mA    41.9mA
-818.2mV  30.8mA     48.91mA    30.91mA
-727.3mV  23.14mA    28.92mA    26.63mA
-636.4mV  19.86mA    18.79mA    22.63mA
-545.5mV  16.97mA    15.28mA    18.88mA
-318.2mV  11.92mA    10.86mA    12.64mA
772.8mV   0A         0A         172.3uA
3V        0A         0A         0A
[GND_clamp]
|   voltage   I(typ)   I(min)   I(max)
-1.5V     -323.8mA   -261.1mA   -417mA
-1.091V   -124.7mA   -123.5mA   -129.5mA
-1.046V   -104mA     -108.9mA   -100.7mA
-954.6mV  -65.51mA   -80.71mA   -51.8mA
-909.2mV  -48.85mA   -67.28mA   -37.69mA
-863.7mV  -35.69mA   -54.58mA   -32.07mA
-818.2mV  -27.65mA   -42.93mA   -29.49mA
-727.3mV  -21.94mA   -25.2mA    -25.43mA
-636.4mV  -18.95mA   -17.58mA   -21.64mA
-545.5mV  -16.34mA   -14.82mA   -18.19mA
772.8mV   0A         0A         -166.5uA
3V        0A         0A         0A
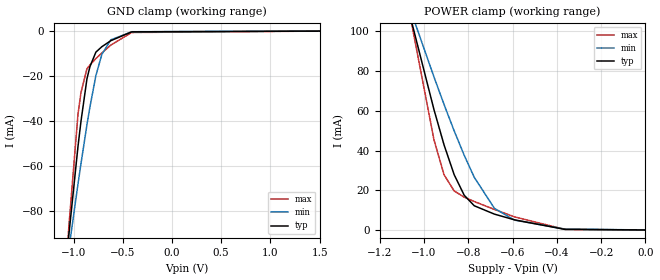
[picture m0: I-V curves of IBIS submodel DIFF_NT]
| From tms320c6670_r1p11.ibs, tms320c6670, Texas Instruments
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|   SubModel Cell DIFF_NT
|DIFF_NT
[Submodel]   DIFF_NT
Submodel_type   Dynamic_clamp
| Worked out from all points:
|   GND clamp passes 1 mA (typ) near -0.47 V on its own axis
|   POWER clamp passes 1 mA (typ) near -0.42 V on its own axis
[POWER_clamp]
|   voltage   I(typ)   I(min)   I(max)
-1.5V     321.7mA    260.6mA    415.9mA
-1.076V   114.2mA    115.8mA    116.9mA
-1.061V   107.2mA    110.9mA    107.1mA
-954.6mV  60.59mA    77.06mA    45.35mA
-909.2mV  42.85mA    63.21mA    27.81mA
-863.7mV  27.9mA     49.99mA    19.69mA
-818.2mV  17.49mA    37.63mA    16.52mA
-772.8mV  12.19mA    26.53mA    14.33mA
-681.9mV  7.985mA    10.89mA    10.33mA
-590.9mV  5.094mA    4.955mA    6.6mA
-363.7mV  298.5uA    465.2uA    297.6uA
0V        1.518nA    24.08nA    367.8pA
[GND_clamp]
|   voltage   I(typ)   I(min)   I(max)
-1.5V     -310.1mA   -250.5mA   -402.5mA
-1.076V   -103.6mA   -106.2mA   -105.2mA
-1.046V   -89.81mA   -96.36mA   -86.02mA
-954.6mV  -51.22mA   -67.87mA   -36.88mA
-924.3mV  -40.08mA   -58.86mA   -27.29mA
-863.7mV  -21.24mA   -41.56mA   -16.73mA
-833.4mV  -15.8mA    -33.75mA   -15.03mA
-772.8mV  -9.345mA   -19.75mA   -12.19mA
-712.2mV  -6.928mA   -10.35mA   -9.704mA
-621.3mV  -4.261mA   -3.896mA   -6.225mA
-409.1mV  -337.1uA   -289.1uA   -618.9uA
1.5V      1.518nA    257.2nA    299pA
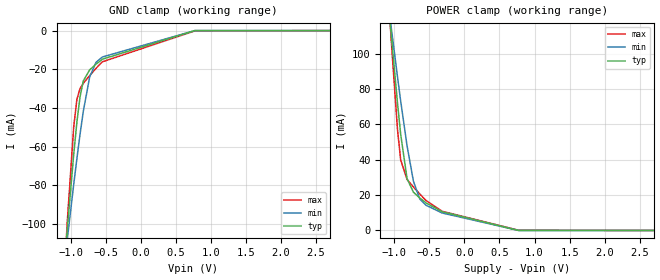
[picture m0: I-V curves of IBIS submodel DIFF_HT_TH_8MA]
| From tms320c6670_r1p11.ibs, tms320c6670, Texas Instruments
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|   Model Cell DIFF_HT_TH_8MA
|DIFF_HT_TH_8MA
[Submodel]   DIFF_HT_TH_8MA
Submodel_type   Dynamic_clamp
[POWER_clamp]
|   voltage   I(typ)   I(min)   I(max)
-1.5V     332mA      268.2mA    426.6mA
-1.091V   132.4mA    130.2mA    138.2mA
-1.046V   111.6mA    115.5mA    108.8mA
-954.6mV  72.07mA    86.93mA    57.17mA
-909.2mV  54.42mA    73.22mA    39.89mA
-818.2mV  29.32mA    47.89mA    28.85mA
-727.3mV  21.64mA    27.88mA    24.58mA
-636.4mV  18.38mA    17.72mA    20.6mA
-545.5mV  15.51mA    14.22mA    16.88mA
-318.2mV  10.6mA     9.888mA    10.85mA
772.8mV   0A         0A         147.9uA
3V        0A         0A         0A
[GND_clamp]
|   voltage   I(typ)   I(min)   I(max)
-1.5V     -322.3mA   -260.1mA   -414.9mA
-1.091V   -123.1mA   -122.4mA   -127.4mA
-1.046V   -102.5mA   -107.8mA   -98.61mA
-954.6mV  -63.92mA   -79.54mA   -49.67mA
-909.2mV  -47.26mA   -66.11mA   -35.51mA
-863.7mV  -34.08mA   -53.39mA   -29.88mA
-818.2mV  -26.03mA   -41.74mA   -27.3mA
-727.3mV  -20.32mA   -24mA      -23.27mA
-636.4mV  -17.36mA   -16.38mA   -19.51mA
-545.5mV  -14.79mA   -13.65mA   -16.12mA
772.8mV   0A         0A         -142.6uA
3V        0A         0A         0A
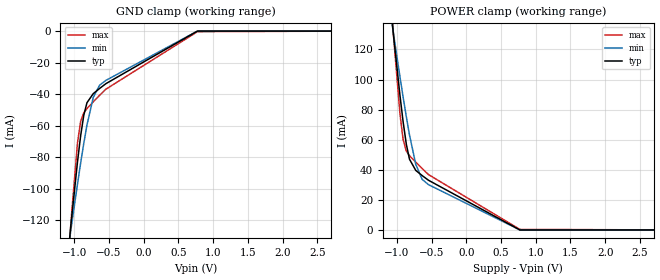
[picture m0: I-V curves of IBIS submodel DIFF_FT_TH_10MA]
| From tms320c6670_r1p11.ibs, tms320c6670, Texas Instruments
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|   Model Cell DIFF_FT_TH_10MA
|DIFF_FT_TH_10MA
[Submodel]   DIFF_FT_TH_10MA
Submodel_type   Dynamic_clamp
[POWER_clamp]
|   voltage   I(typ)   I(min)   I(max)
-1.5V     347.4mA    279.5mA    444.5mA
-1.091V   149.3mA    144.3mA    157.4mA
-1.046V   128.6mA    129.8mA    128.2mA
-954.6mV  89.29mA    101.7mA    76.89mA
-909.2mV  71.77mA    88.24mA    60.03mA
-863.7mV  57.1mA     75.34mA    52.47mA
-818.2mV  47.07mA    63.28mA    49.41mA
-727.3mV  39.57mA    43.6mA     45.05mA
-636.4mV  36.2mA     33.7mA     40.88mA
-545.5mV  33.08mA    30.16mA    36.86mA
772.8mV   0A         0A         392.4uA
3V        0A         0A         0A
[GND_clamp]
|   voltage   I(typ)   I(min)   I(max)
-1.5V     -340.5mA   -274.6mA   -435.6mA
-1.091V   -142mA     -139.4mA   -148.4mA
-1.046V   -121.5mA   -125mA     -119.6mA
-954.6mV  -82.98mA   -97.05mA   -70.99mA
-909.2mV  -66.39mA   -83.75mA   -57.24mA
-863.7mV  -53.35mA   -71.15mA   -51.78mA
-818.2mV  -45.45mA   -59.59mA   -49.15mA
-727.3mV  -39.68mA   -42.01mA   -44.86mA
-636.4mV  -36.4mA    -34.36mA   -40.75mA
-545.5mV  -33.35mA   -31.26mA   -36.85mA
772.8mV   0A         0A         -381uA
3V        0A         0A         0A
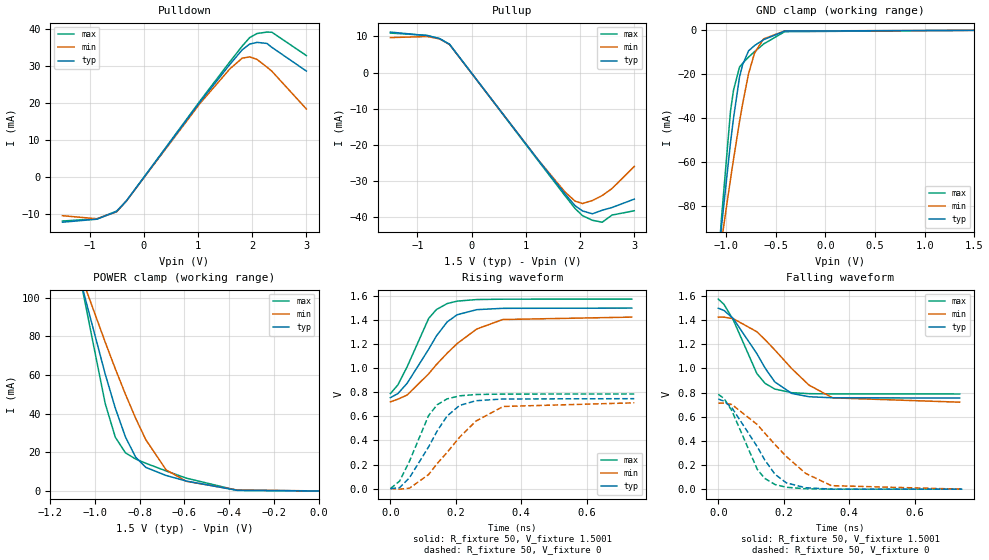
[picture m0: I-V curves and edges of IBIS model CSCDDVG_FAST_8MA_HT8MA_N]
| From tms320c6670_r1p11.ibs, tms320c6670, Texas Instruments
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|   Model Cell CSCDDVG_FAST_8MA_HT8MA_N
[Model]   CSCDDVG_FAST_8MA_HT8MA_N
Model_type   I/O
Polarity   Non-Inverting
Enable   Active-Low
Cref =  4.0000pF
Rref =  100.0000M
Vref =  0V
Vmeas =  0.75
C_comp   1.5249p   1.4275p   1.6205p
|[mode_tieoffpin] SR0=1  SR1=0 I0=0 I1=0 I2=1
[Model Spec]
Vinl   0.6125   0.6125   0.6125
Vinh   0.9625   0.9625   0.9625
D_overshoot_high 1.95 1.95 1.95
D_overshoot_low -0.3 -0.3 -0.3
D_overshoot_time 1E-9 1E-9 1E-9
S_overshoot_high 1.575 1.575 1.575
S_overshoot_low 0 0 0
[Receiver Thresholds]
Vcross_low = 0.5625V
Vcross_high = 0.9375V
Vdiff_ac = +350mV
Vdiff_dc = +200mV
Tdiffslew_ac = 350ps
[Add Submodel]|Submodel_name Mode
DIFF_HT_TH_8MA Non-Driving
[Temperature Range]   25   105   -40
[Voltage Range]   1.5   1.425   1.575
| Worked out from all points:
|   slope of the pulldown table from 0 to 0.225 V, typ, clamps not added: 50.1 ohm
|   slope of the pullup table from 0 to 0.225 V, typ, clamps not added: 50.1 ohm
|   GND clamp passes 1 mA (typ) near -0.47 V on its own axis
|   POWER clamp passes 1 mA (typ) near -0.42 V on its own axis
|   rising waveform, R_fixture 50, V_fixture 1.5001: 20-80 % time 103ps typ, 154ps min, 78.3ps max; typ from 0.756 V to 1.5 V
|   rising waveform, R_fixture 50, V_fixture 0: 20-80 % time 99.2ps typ, 141ps min, 75.3ps max; typ from 0 V to 0.747 V
|   falling waveform, R_fixture 50, V_fixture 1.5001: 20-80 % time 104ps typ, 152ps min, 78ps max; typ from 1.5 V to 0.755 V
|   falling waveform, R_fixture 50, V_fixture 0: 20-80 % time 101ps typ, 154ps min, 75.5ps max; typ from 0.747 V to 0 V
[POWER_clamp]
|   voltage   I(typ)   I(min)   I(max)
-1.5V     321.7mA    260.6mA    415.9mA
-1.076V   114.2mA    115.8mA    116.9mA
-1.061V   107.2mA    110.9mA    107.1mA
-954.6mV  60.59mA    77.06mA    45.35mA
-909.2mV  42.85mA    63.21mA    27.81mA
-863.7mV  27.9mA     49.99mA    19.69mA
-818.2mV  17.49mA    37.63mA    16.52mA
-772.8mV  12.19mA    26.53mA    14.33mA
-681.9mV  7.985mA    10.89mA    10.33mA
-590.9mV  5.094mA    4.955mA    6.6mA
-363.7mV  298.5uA    465.2uA    297.6uA
0V        1.518nA    24.08nA    367.8pA
[Pulldown]
|   voltage   I(typ)   I(min)   I(max)
-1.5V     -12.15mA   -10.4mA    -11.83mA
-863.7mV  -11.34mA   -11.22mA   -11.25mA
-500mV    -9.267mA   -9.352mA   -9.148mA
-318.2mV  -6.354mA   -6.371mA   -6.385mA
1.046V    20.42mA    20.05mA    20.72mA
1.591V    30.47mA    29.26mA    31.18mA
1.818V    34.39mA    32.13mA    35.4mA
1.955V    35.92mA    32.45mA    37.67mA
2.091V    36.38mA    31.76mA    38.77mA
2.273V    36.08mA    29.69mA    39.15mA
2.364V    35.03mA    28.59mA    39.11mA
3V        28.64mA    18.41mA    32.82mA
[Pullup]
|   voltage   I(typ)   I(min)   I(max)
-1.5V     11.21mA    9.69mA     10.94mA
-818.2mV  10.23mA    9.978mA    10.29mA
-590.9mV  9.401mA    9.328mA    9.374mA
-409.1mV  7.828mA    7.781mA    7.859mA
1.227V    -24.14mA   -24.11mA   -24.35mA
1.727V    -33.63mA   -33.09mA   -34.13mA
1.909V    -36.81mA   -35.55mA   -37.6mA
2.046V    -38.25mA   -36.2mA    -39.57mA
2.227V    -39.04mA   -35.36mA   -40.83mA
2.409V    -38.05mA   -33.98mA   -41.36mA
2.591V    -37.29mA   -32.03mA   -39.38mA
3V        -34.98mA   -25.95mA   -38.2mA
[GND_clamp]
|   voltage   I(typ)   I(min)   I(max)
-1.5V     -310.1mA   -250.5mA   -402.5mA
-1.076V   -103.6mA   -106.2mA   -105.2mA
-1.046V   -89.81mA   -96.36mA   -86.02mA
-954.6mV  -51.22mA   -67.87mA   -36.88mA
-924.3mV  -40.08mA   -58.86mA   -27.29mA
-863.7mV  -21.24mA   -41.56mA   -16.73mA
-833.4mV  -15.8mA    -33.75mA   -15.03mA
-772.8mV  -9.345mA   -19.75mA   -12.19mA
-712.2mV  -6.928mA   -10.35mA   -9.704mA
-621.3mV  -4.261mA   -3.896mA   -6.225mA
-409.1mV  -337.1uA   -289.1uA   -618.9uA
1.5V      1.518nA    257.2nA    299pA
[Ramp]
| variable   typ   min   max
dV/dt_f   0.596008/0.15568375n   0.563744/0.22543869n   0.629272/0.12060237n
dV/dt_r 0.60140536/0.14772322n 0.57539688/0.2137572n 0.63083936/0.1163411n
R_load = 50
[Rising Waveform]
R_fixture = 50
V_fixture = 1.5001
V_fixture_min = 1.425
V_fixture_max = 1.575
|   time   V(typ)   V(min)   V(max)
0s        755.9mV    721.1mV    789.3mV
22.94ps   789.5mV    743.1mV    861.8mV
51ps      874.4mV    777.1mV    1.011V
117.2ps   1.159V     954.1mV    1.415V
140.8ps   1.269V     1.031V     1.488V
173.9ps   1.386V     1.126V     1.538V
204.4ps   1.445V     1.206V     1.558V
264ps     1.487V     1.326V     1.571V
343.2ps   1.498V     1.405V     1.574V
737.8ps   1.5V       1.425V     1.575V
[Rising Waveform]
R_fixture = 50
V_fixture = 0
V_fixture_min = 0
V_fixture_max = 0
|   time   V(typ)   V(min)   V(max)
0s        0V         0V         0V
28.14ps   7.541mV    -4.591mV   62.2mV
58.42ps   90.69mV    3.723mV    228mV
116.7ps   346.3mV    116.7mV    606.8mV
142.8ps   477.9mV    207.3mV    696.5mV
173.2ps   603mV      300.3mV    745.4mV
211.6ps   691mV      426.9mV    770.9mV
261.7ps   730.4mV    561.5mV    781.9mV
344.7ps   744.8mV    682.5mV    785.5mV
745.5ps   747.3mV    712.8mV    786.3mV
[Falling Waveform]
R_fixture = 50
V_fixture = 1.5001
V_fixture_min = 1.425
V_fixture_max = 1.575
|   time   V(typ)   V(min)   V(max)
0s        1.499V     1.425V     1.575V
17.41ps   1.481V     1.425V     1.531V
45.47ps   1.414V     1.413V     1.404V
118ps     1.122V     1.304V     957.1mV
143.1ps   1.003V     1.238V     876.6mV
172.6ps   888.9mV    1.154V     829.6mV
224.3ps   793.4mV    999.4mV    799.4mV
277.2ps   765.8mV    862.1mV    791.2mV
349.4ps   757.1mV    756.7mV    789.1mV
737.8ps   755.2mV    720.6mV    788.5mV
[Falling Waveform]
R_fixture = 50
V_fixture = 0
V_fixture_min = 0
V_fixture_max = 0
|   time   V(typ)   V(min)   V(max)
0s        746.6mV    712.3mV    785.4mV
17.41ps   729mV      712.9mV    751.7mV
41.16ps   676.2mV    701.7mV    651.5mV
119.2ps   351.2mV    534.9mV    163.9mV
141.7ps   243.4mV    465.5mV    89.64mV
173.6ps   122.2mV    368.9mV    38.12mV
208ps     52.13mV    270.4mV    15.57mV
266.9ps   12.07mV    130.9mV    3.438mV
345.7ps   0V         29.15mV    0V
745.5ps   0V         0V         0V
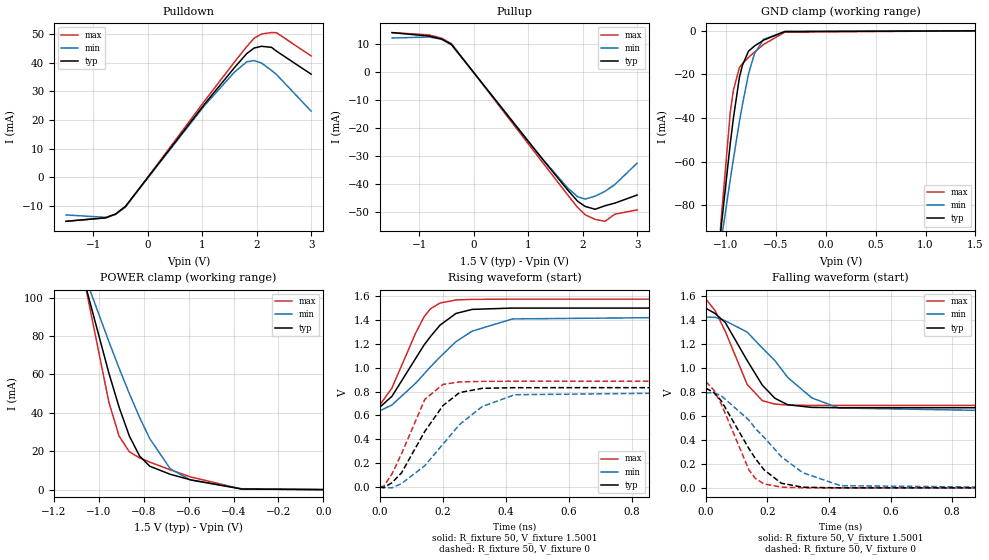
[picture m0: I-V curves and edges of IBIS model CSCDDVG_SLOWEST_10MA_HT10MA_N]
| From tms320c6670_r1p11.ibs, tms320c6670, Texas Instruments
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|   Model Cell CSCDDVG_SLOWEST_10MA_HT10MA_N
|SLOWEST_10MA
[Model]   CSCDDVG_SLOWEST_10MA_HT10MA_N
Model_type   I/O
Polarity   Non-Inverting
Enable   Active-Low
Cref =  4.0000pF
Rref =  100.0000M
Vref =  0V
Vmeas =  0.75
C_comp   1.5249p   1.4275p   1.6205p
|[mode_tieoffpin] SR0=1  SR1=1 I0=0 I1=1 I2=1
[Model Spec]
Vinl   0.6125   0.6125   0.6125
Vinh   0.9625   0.9625   0.9625
D_overshoot_high 1.95 1.95 1.95
D_overshoot_low -0.3 -0.3 -0.3
D_overshoot_time 1E-9 1E-9 1E-9
S_overshoot_high 1.575 1.575 1.575
S_overshoot_low 0 0 0
[Receiver Thresholds]
Vcross_low = 0.5625V
Vcross_high = 0.9375V
Vdiff_ac = +350mV
Vdiff_dc = +200mV
Tdiffslew_ac = 350ps
[Add Submodel]|Submodel_name Mode
DIFF_HT_TH_10MA Non-Driving
[Temperature Range]   25   105   -40
[Voltage Range]   1.5   1.425   1.575
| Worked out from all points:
|   slope of the pulldown table from 0 to 0.225 V, typ, clamps not added: 39.9 ohm
|   slope of the pullup table from 0 to 0.225 V, typ, clamps not added: 39.8 ohm
|   GND clamp passes 1 mA (typ) near -0.47 V on its own axis
|   POWER clamp passes 1 mA (typ) near -0.42 V on its own axis
|   rising waveform, R_fixture 50, V_fixture 1.5001: 20-80 % time 123ps typ, 181ps min, 89.8ps max; typ from 0.669 V to 1.5 V
|   rising waveform, R_fixture 50, V_fixture 0: 20-80 % time 115ps typ, 170ps min, 87.7ps max; typ from 0 V to 0.834 V
|   falling waveform, R_fixture 50, V_fixture 1.5001: 20-80 % time 117ps typ, 176ps min, 87.6ps max; typ from 1.5 V to 0.669 V
|   falling waveform, R_fixture 50, V_fixture 0: 20-80 % time 118ps typ, 181ps min, 85.8ps max; typ from 0.833 V to 0 V
[POWER_clamp]
|   voltage   I(typ)   I(min)   I(max)
-1.5V     321.7mA    260.6mA    415.9mA
-1.076V   114.2mA    115.8mA    116.9mA
-1.061V   107.2mA    110.9mA    107.1mA
-954.6mV  60.59mA    77.06mA    45.35mA
-909.2mV  42.85mA    63.21mA    27.81mA
-863.7mV  27.9mA     49.99mA    19.69mA
-818.2mV  17.49mA    37.63mA    16.52mA
-772.8mV  12.19mA    26.53mA    14.33mA
-681.9mV  7.985mA    10.89mA    10.33mA
-590.9mV  5.094mA    4.955mA    6.6mA
-363.7mV  298.5uA    465.2uA    297.6uA
0V        1.518nA    24.08nA    367.8pA
[Pulldown]
|   voltage   I(typ)   I(min)   I(max)
-1.5V     -15.29mA   -13.07mA   -15.28mA
-772.8mV  -14.07mA   -13.9mA    -14.11mA
-590.9mV  -12.74mA   -12.86mA   -12.82mA
-409.1mV  -10.08mA   -10.11mA   -10.32mA
1.046V    25.68mA    25.17mA    26.75mA
1.591V    38.31mA    36.75mA    40.25mA
1.818V    43.24mA    40.36mA    45.69mA
1.955V    45.18mA    40.77mA    48.64mA
2.091V    45.77mA    39.91mA    50.06mA
2.273V    45.4mA     37.32mA    50.56mA
2.364V    44.07mA    35.93mA    50.51mA
3V        36.04mA    23.14mA    42.4mA
[Pullup]
|   voltage   I(typ)   I(min)   I(max)
-1.5V     14.1mA     12.18mA    14.13mA
-818.2mV  12.87mA    12.54mA    13.29mA
-590.9mV  11.83mA    11.72mA    12.11mA
-409.1mV  9.844mA    9.773mA    10.15mA
1.227V    -30.36mA   -30.27mA   -31.43mA
1.727V    -42.29mA   -41.55mA   -44.05mA
1.909V    -46.29mA   -44.65mA   -48.54mA
2.046V    -48.11mA   -45.48mA   -51.1mA
2.227V    -49.12mA   -44.44mA   -52.74mA
2.409V    -47.87mA   -42.71mA   -53.43mA
2.591V    -46.92mA   -40.26mA   -50.87mA
3V        -44.02mA   -32.61mA   -49.35mA
[GND_clamp]
|   voltage   I(typ)   I(min)   I(max)
-1.5V     -310.1mA   -250.5mA   -402.5mA
-1.076V   -103.6mA   -106.2mA   -105.2mA
-1.046V   -89.81mA   -96.36mA   -86.02mA
-954.6mV  -51.22mA   -67.87mA   -36.88mA
-924.3mV  -40.08mA   -58.86mA   -27.29mA
-863.7mV  -21.24mA   -41.56mA   -16.73mA
-833.4mV  -15.8mA    -33.75mA   -15.03mA
-772.8mV  -9.345mA   -19.75mA   -12.19mA
-712.2mV  -6.928mA   -10.35mA   -9.704mA
-621.3mV  -4.261mA   -3.896mA   -6.225mA
-409.1mV  -337.1uA   -289.1uA   -618.9uA
1.5V      1.518nA    257.2nA    299pA
[Ramp]
| variable   typ   min   max
dV/dt_f   0.665552/0.1725485n   0.63044/0.26973069n   0.71/0.12908649n
dV/dt_r 0.67150528/0.17522791n 0.64148776/0.26571247n 0.71207976/0.1283244n
R_load = 50
[Rising Waveform]
R_fixture = 50
V_fixture = 1.5001
V_fixture_min = 1.425
V_fixture_max = 1.575
|   time   V(typ)   V(min)   V(max)
0s        669.3mV    639.1mV    688.4mV
38.47ps   760.8mV    687.9mV    830.9mV
114.4ps   1.081V     872.2mV    1.295V
140.5ps   1.191V     947.7mV    1.427V
160.6ps   1.261V     1.007V     1.494V
191.1ps   1.357V     1.09V      1.542V
241.8ps   1.455V     1.219V     1.568V
293.3ps   1.489V     1.307V     1.573V
421ps     1.5V       1.409V     1.575V
1.085ns   1.5V       1.425V     1.575V
[Rising Waveform]
R_fixture = 50
V_fixture = 0
V_fixture_min = 0
V_fixture_max = 0
|   time   V(typ)   V(min)   V(max)
0s        0V         0V         0V
12.29ps   -5.592mV   -3.858mV   7.375mV
38.57ps   36.78mV    -6.579mV   110.1mV
68.76ps   119.2mV    29.05mV    278.8mV
142.8ps   466.8mV    179.4mV    734.9mV
200.2ps   682.2mV    359.2mV    860.3mV
253ps     791.7mV    523.7mV    881mV
325.3ps   827.7mV    675.1mV    885.9mV
428ps     833mV      773.8mV    886.7mV
1.178ns   833.5mV    794.6mV    886.9mV
[Falling Waveform]
R_fixture = 50
V_fixture = 1.5001
V_fixture_min = 1.425
V_fixture_max = 1.575
|   time   V(typ)   V(min)   V(max)
0s        1.499V     1.425V     1.575V
30.01ps   1.455V     1.424V     1.479V
63.19ps   1.379V     1.394V     1.305V
134.1ps   1.063V     1.3V       863.4mV
183.3ps   857.1mV    1.167V     727.5mV
224.2ps   747.7mV    1.062V     699.2mV
265.9ps   693.4mV    921.3mV    691.3mV
344.2ps   671.4mV    750.8mV    688.1mV
431.3ps   668.9mV    666.6mV    687.8mV
1.085ns   668.6mV    638.1mV    687.6mV
[Falling Waveform]
R_fixture = 50
V_fixture = 0
V_fixture_min = 0
V_fixture_max = 0
|   time   V(typ)   V(min)   V(max)
0s        832.6mV    793.6mV    886mV
26.42ps   793.5mV    793.1mV    814.9mV
49.92ps   726.6mV    768.8mV    700.6mV
139.9ps   326.6mV    565.9mV    149.6mV
160.4ps   245.9mV    496mV      79.57mV
188.9ps   150.7mV    422.4mV    32.71mV
245.3ps   38.4mV     259.7mV    6.156mV
315ps     5.434mV    126mV      0V
437.8ps   0V         17.97mV    0V
1.178ns   0V         0V         0V
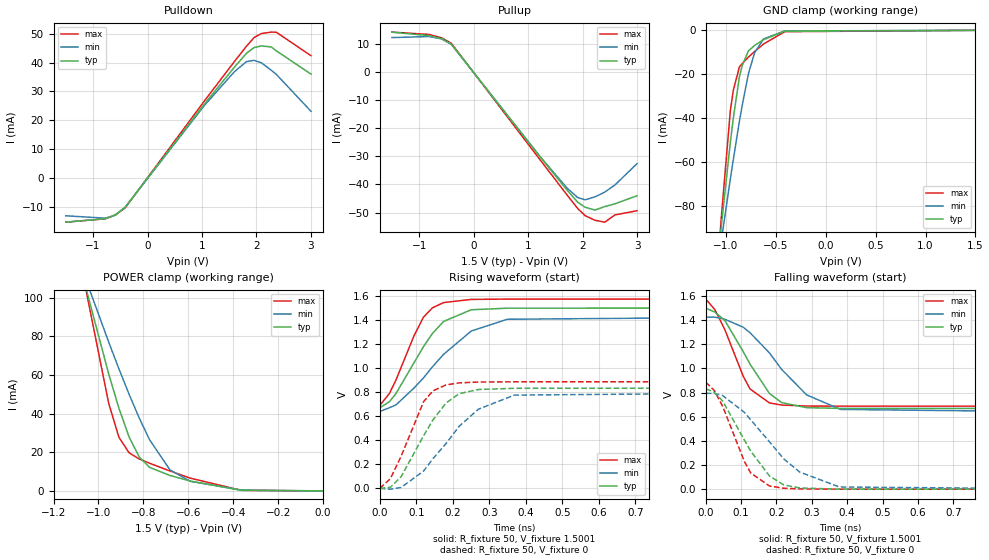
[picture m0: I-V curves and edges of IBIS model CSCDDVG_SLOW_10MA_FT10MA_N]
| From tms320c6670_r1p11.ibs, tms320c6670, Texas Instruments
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|   Model Cell CSCDDVG_SLOW_10MA_FT10MA_N
|SLOW_10MA
[Model]   CSCDDVG_SLOW_10MA_FT10MA_N
Model_type   I/O
Polarity   Non-Inverting
Enable   Active-Low
Cref =  4.0000pF
Rref =  100.0000M
Vref =  0V
Vmeas =  0.75
C_comp   1.5249p   1.4275p   1.6205p
|[mode_tieoffpin] SR0=0  SR1=1 I0=0 I1=1 I2=1
[Model Spec]
Vinl   0.6125   0.6125   0.6125
Vinh   0.9625   0.9625   0.9625
D_overshoot_high 1.95 1.95 1.95
D_overshoot_low -0.3 -0.3 -0.3
D_overshoot_time 1E-9 1E-9 1E-9
S_overshoot_high 1.575 1.575 1.575
S_overshoot_low 0 0 0
[Receiver Thresholds]
Vcross_low = 0.5625V
Vcross_high = 0.9375V
Vdiff_ac = +350mV
Vdiff_dc = +200mV
Tdiffslew_ac = 350ps
[Add Submodel]|Submodel_name Mode
DIFF_FT_TH_10MA Non-Driving
[Temperature Range]   25   105   -40
[Voltage Range]   1.5   1.425   1.575
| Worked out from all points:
|   slope of the pulldown table from 0 to 0.225 V, typ, clamps not added: 39.9 ohm
|   slope of the pullup table from 0 to 0.225 V, typ, clamps not added: 39.8 ohm
|   GND clamp passes 1 mA (typ) near -0.47 V on its own axis
|   POWER clamp passes 1 mA (typ) near -0.42 V on its own axis
|   rising waveform, R_fixture 50, V_fixture 1.5001: 20-80 % time 102ps typ, 147ps min, 75.6ps max; typ from 0.669 V to 1.5 V
|   rising waveform, R_fixture 50, V_fixture 0: 20-80 % time 96.4ps typ, 137ps min, 73ps max; typ from 0 V to 0.834 V
|   falling waveform, R_fixture 50, V_fixture 1.5001: 20-80 % time 99.2ps typ, 145ps min, 75.9ps max; typ from 1.5 V to 0.669 V
|   falling waveform, R_fixture 50, V_fixture 0: 20-80 % time 101ps typ, 148ps min, 73.9ps max; typ from 0.833 V to 0 V
[POWER_clamp]
|   voltage   I(typ)   I(min)   I(max)
-1.5V     321.7mA    260.6mA    415.9mA
-1.076V   114.2mA    115.8mA    116.9mA
-1.061V   107.2mA    110.9mA    107.1mA
-954.6mV  60.59mA    77.06mA    45.35mA
-909.2mV  42.85mA    63.21mA    27.81mA
-863.7mV  27.9mA     49.99mA    19.69mA
-818.2mV  17.49mA    37.63mA    16.52mA
-772.8mV  12.19mA    26.53mA    14.33mA
-681.9mV  7.985mA    10.89mA    10.33mA
-590.9mV  5.094mA    4.955mA    6.6mA
-363.7mV  298.5uA    465.2uA    297.6uA
0V        1.518nA    24.08nA    367.8pA
[Pulldown]
|   voltage   I(typ)   I(min)   I(max)
-1.5V     -15.29mA   -13.07mA   -15.28mA
-772.8mV  -14.07mA   -13.9mA    -14.11mA
-590.9mV  -12.74mA   -12.86mA   -12.82mA
-409.1mV  -10.08mA   -10.11mA   -10.32mA
1.046V    25.68mA    25.17mA    26.75mA
1.591V    38.31mA    36.75mA    40.25mA
1.818V    43.24mA    40.36mA    45.69mA
1.955V    45.18mA    40.77mA    48.64mA
2.091V    45.77mA    39.91mA    50.06mA
2.273V    45.4mA     37.32mA    50.56mA
2.364V    44.07mA    35.93mA    50.51mA
3V        36.04mA    23.14mA    42.4mA
[Pullup]
|   voltage   I(typ)   I(min)   I(max)
-1.5V     14.1mA     12.18mA    14.13mA
-818.2mV  12.87mA    12.54mA    13.29mA
-590.9mV  11.83mA    11.72mA    12.11mA
-409.1mV  9.844mA    9.773mA    10.15mA
1.227V    -30.36mA   -30.27mA   -31.43mA
1.727V    -42.29mA   -41.55mA   -44.05mA
1.909V    -46.29mA   -44.65mA   -48.54mA
2.046V    -48.11mA   -45.48mA   -51.1mA
2.227V    -49.12mA   -44.44mA   -52.74mA
2.409V    -47.87mA   -42.71mA   -53.43mA
2.591V    -46.92mA   -40.26mA   -50.87mA
3V        -44.02mA   -32.61mA   -49.35mA
[GND_clamp]
|   voltage   I(typ)   I(min)   I(max)
-1.5V     -310.1mA   -250.5mA   -402.5mA
-1.076V   -103.6mA   -106.2mA   -105.2mA
-1.046V   -89.81mA   -96.36mA   -86.02mA
-954.6mV  -51.22mA   -67.87mA   -36.88mA
-924.3mV  -40.08mA   -58.86mA   -27.29mA
-863.7mV  -21.24mA   -41.56mA   -16.73mA
-833.4mV  -15.8mA    -33.75mA   -15.03mA
-772.8mV  -9.345mA   -19.75mA   -12.19mA
-712.2mV  -6.928mA   -10.35mA   -9.704mA
-621.3mV  -4.261mA   -3.896mA   -6.225mA
-409.1mV  -337.1uA   -289.1uA   -618.9uA
1.5V      1.518nA    257.2nA    299pA
[Ramp]
| variable   typ   min   max
dV/dt_f   0.665312/0.14716328n   0.63012/0.22330251n   0.71/0.11480851n
dV/dt_r 0.67173512/0.14256136n 0.64143768/0.21543312n 0.71245768/0.10990193n
R_load = 50
[Rising Waveform]
R_fixture = 50
V_fixture = 1.5001
V_fixture_min = 1.425
V_fixture_max = 1.575
|   time   V(typ)   V(min)   V(max)
0s        669.3mV    639.1mV    688.4mV
26.95ps   722.1mV    671.4mV    790.8mV
44.61ps   788.4mV    694.7mV    901.6mV
93.68ps   1.044V     833.9mV    1.267V
119.5ps   1.177V     917.6mV    1.423V
144.3ps   1.289V     1.011V     1.502V
175.2ps   1.389V     1.116V     1.546V
250.5ps   1.486V     1.309V     1.572V
349.2ps   1.499V     1.407V     1.575V
1.091ns   1.5V       1.425V     1.575V
[Rising Waveform]
R_fixture = 50
V_fixture = 0
V_fixture_min = 0
V_fixture_max = 0
|   time   V(typ)   V(min)   V(max)
0s        0V         0V         0V
29.33ps   9.547mV    -6.305mV   80.41mV
58.47ps   96.39mV    7.323mV    266mV
120.1ps   437.3mV    144.2mV    720.9mV
145.7ps   569mV      246.4mV    811.2mV
181.4ps   709.7mV    372.4mV    860.5mV
217.6ps   788.4mV    516.8mV    877.8mV
270.2ps   822.7mV    659.1mV    884.7mV
368.9ps   832.6mV    776.2mV    886.6mV
1.099ns   833.5mV    794.6mV    886.9mV
[Falling Waveform]
R_fixture = 50
V_fixture = 1.5001
V_fixture_min = 1.425
V_fixture_max = 1.575
|   time   V(typ)   V(min)   V(max)
0s        1.499V     1.425V     1.575V
25.52ps   1.468V     1.425V     1.488V
53.89ps   1.398V     1.408V     1.322V
105.7ps   1.141V     1.342V     937.2mV
125.2ps   1.036V     1.296V     830.1mV
180.1ps   792.9mV    1.129V     714.5mV
214.5ps   717.3mV    992.6mV    697mV
285.2ps   675.3mV    781.1mV    688.9mV
381.4ps   669.1mV    660.5mV    687.8mV
1.091ns   668.6mV    638.1mV    687.6mV
[Falling Waveform]
R_fixture = 50
V_fixture = 0
V_fixture_min = 0
V_fixture_max = 0
|   time   V(typ)   V(min)   V(max)
0s        832.6mV    794.3mV    886mV
24.12ps   802.1mV    794mV      817.5mV
48.11ps   728.8mV    774.7mV    684.1mV
108.9ps   408.2mV    637.1mV    231.9mV
127.1ps   315.2mV    574.5mV    134.2mV
180.3ps   109mV      392.4mV    25.85mV
220.6ps   35.36mV    250.8mV    7.842mV
265.9ps   9.9mV      141.2mV    2.068mV
377.7ps   0V         18.16mV    0V
1.099ns   0V         0V         0V
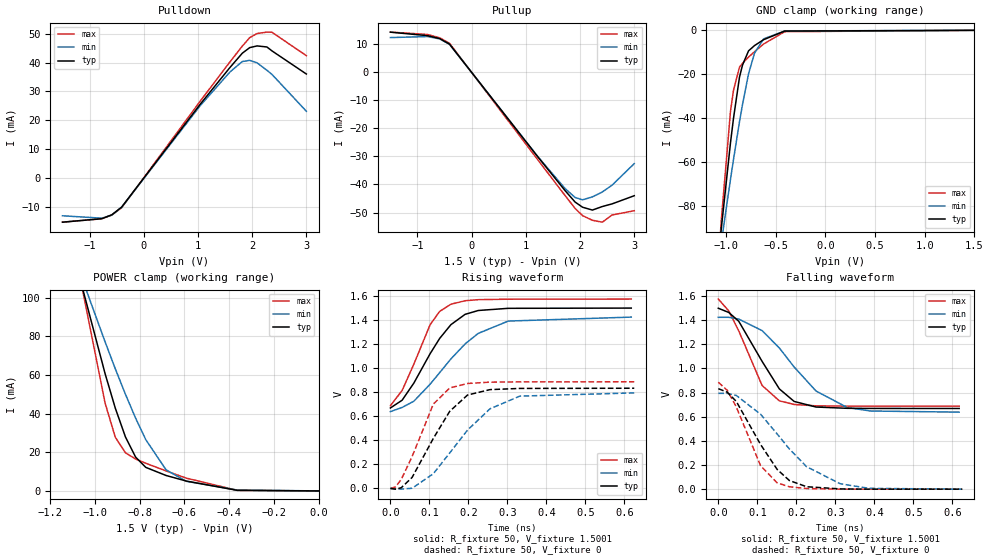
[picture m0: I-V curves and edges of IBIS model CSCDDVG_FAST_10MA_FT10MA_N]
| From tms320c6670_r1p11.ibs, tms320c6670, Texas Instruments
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|   Model Cell CSCDDVG_FAST_10MA_FT10MA_N
|FAST_10MA
[Model]   CSCDDVG_FAST_10MA_FT10MA_N
Model_type   I/O
Polarity   Non-Inverting
Enable   Active-Low
Cref =  4.0000pF
Rref =  100.0000M
Vref =  0V
Vmeas =  0.75
C_comp   1.5249p   1.4275p   1.6205p
|[mode_tieoffpin] SR0=1  SR1=0 I0=0 I1=1 I2=1
[Model Spec]
Vinl   0.6125   0.6125   0.6125
Vinh   0.9625   0.9625   0.9625
D_overshoot_high 1.95 1.95 1.95
D_overshoot_low -0.3 -0.3 -0.3
D_overshoot_time 1E-9 1E-9 1E-9
S_overshoot_high 1.575 1.575 1.575
S_overshoot_low 0 0 0
[Receiver Thresholds]
Vcross_low = 0.5625V
Vcross_high = 0.9375V
Vdiff_ac = +350mV
Vdiff_dc = +200mV
Tdiffslew_ac = 350ps
[Add Submodel]|Submodel_name Mode
DIFF_FT_TH_10MA Non-Driving
[Temperature Range]   25   105   -40
[Voltage Range]   1.5   1.425   1.575
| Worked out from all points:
|   slope of the pulldown table from 0 to 0.225 V, typ, clamps not added: 39.9 ohm
|   slope of the pullup table from 0 to 0.225 V, typ, clamps not added: 39.8 ohm
|   GND clamp passes 1 mA (typ) near -0.47 V on its own axis
|   POWER clamp passes 1 mA (typ) near -0.42 V on its own axis
|   rising waveform, R_fixture 50, V_fixture 1.5001: 20-80 % time 94.2ps typ, 135ps min, 71.8ps max; typ from 0.669 V to 1.5 V
|   rising waveform, R_fixture 50, V_fixture 0: 20-80 % time 89ps typ, 126ps min, 68ps max; typ from 0 V to 0.834 V
|   falling waveform, R_fixture 50, V_fixture 1.5001: 20-80 % time 90.7ps typ, 130ps min, 71.1ps max; typ from 1.5 V to 0.669 V
|   falling waveform, R_fixture 50, V_fixture 0: 20-80 % time 92.1ps typ, 133ps min, 69.2ps max; typ from 0.833 V to 0 V
[POWER_clamp]
|   voltage   I(typ)   I(min)   I(max)
-1.5V     321.7mA    260.6mA    415.9mA
-1.076V   114.2mA    115.8mA    116.9mA
-1.061V   107.2mA    110.9mA    107.1mA
-954.6mV  60.59mA    77.06mA    45.35mA
-909.2mV  42.85mA    63.21mA    27.81mA
-863.7mV  27.9mA     49.99mA    19.69mA
-818.2mV  17.49mA    37.63mA    16.52mA
-772.8mV  12.19mA    26.53mA    14.33mA
-681.9mV  7.985mA    10.89mA    10.33mA
-590.9mV  5.094mA    4.955mA    6.6mA
-363.7mV  298.5uA    465.2uA    297.6uA
0V        1.518nA    24.08nA    367.8pA
[Pulldown]
|   voltage   I(typ)   I(min)   I(max)
-1.5V     -15.29mA   -13.07mA   -15.28mA
-772.8mV  -14.07mA   -13.9mA    -14.11mA
-590.9mV  -12.74mA   -12.86mA   -12.82mA
-409.1mV  -10.08mA   -10.11mA   -10.32mA
1.046V    25.68mA    25.17mA    26.75mA
1.591V    38.31mA    36.75mA    40.25mA
1.818V    43.24mA    40.36mA    45.69mA
1.955V    45.18mA    40.77mA    48.64mA
2.091V    45.77mA    39.91mA    50.06mA
2.273V    45.4mA     37.32mA    50.56mA
2.364V    44.07mA    35.93mA    50.51mA
3V        36.04mA    23.14mA    42.4mA
[Pullup]
|   voltage   I(typ)   I(min)   I(max)
-1.5V     14.1mA     12.18mA    14.13mA
-818.2mV  12.87mA    12.54mA    13.29mA
-590.9mV  11.83mA    11.72mA    12.11mA
-409.1mV  9.844mA    9.773mA    10.15mA
1.227V    -30.36mA   -30.27mA   -31.43mA
1.727V    -42.29mA   -41.55mA   -44.05mA
1.909V    -46.29mA   -44.65mA   -48.54mA
2.046V    -48.11mA   -45.48mA   -51.1mA
2.227V    -49.12mA   -44.44mA   -52.74mA
2.409V    -47.87mA   -42.71mA   -53.43mA
2.591V    -46.92mA   -40.26mA   -50.87mA
3V        -44.02mA   -32.61mA   -49.35mA
[GND_clamp]
|   voltage   I(typ)   I(min)   I(max)
-1.5V     -310.1mA   -250.5mA   -402.5mA
-1.076V   -103.6mA   -106.2mA   -105.2mA
-1.046V   -89.81mA   -96.36mA   -86.02mA
-954.6mV  -51.22mA   -67.87mA   -36.88mA
-924.3mV  -40.08mA   -58.86mA   -27.29mA
-863.7mV  -21.24mA   -41.56mA   -16.73mA
-833.4mV  -15.8mA    -33.75mA   -15.03mA
-772.8mV  -9.345mA   -19.75mA   -12.19mA
-712.2mV  -6.928mA   -10.35mA   -9.704mA
-621.3mV  -4.261mA   -3.896mA   -6.225mA
-409.1mV  -337.1uA   -289.1uA   -618.9uA
1.5V      1.518nA    257.2nA    299pA
[Ramp]
| variable   typ   min   max
dV/dt_f   0.665384/0.13628682n   0.629864/0.2000188n   0.71/0.10897595n
dV/dt_r  0.6716992/0.13165568n 0.64196624/0.19536277n 0.71221096/0.10400915n
R_load = 50
[Rising Waveform]
R_fixture = 50
V_fixture = 1.5001
V_fixture_min = 1.425
V_fixture_max = 1.575
|   time   V(typ)   V(min)   V(max)
0s        669.3mV    639.1mV    688.4mV
30.11ps   734mV      673.6mV    814.7mV
60.19ps   876.5mV    725.6mV    1.034V
101.7ps   1.12V      866.7mV    1.361V
126.4ps   1.248V     963.5mV    1.473V
155.1ps   1.362V     1.077V     1.532V
191.5ps   1.448V     1.202V     1.561V
225.4ps   1.48V      1.29V      1.57V
302.2ps   1.498V     1.392V     1.574V
617.4ps   1.5V       1.425V     1.575V
[Rising Waveform]
R_fixture = 50
V_fixture = 0
V_fixture_min = 0
V_fixture_max = 0
|   time   V(typ)   V(min)   V(max)
0s        0V         0V         0V
13.22ps   -5.968mV   -2.685mV   12.57mV
27.88ps   5.983mV    -5.338mV   75.12mV
55.63ps   91.65mV    1.606mV    264.6mV
110.1ps   416.3mV    122.5mV    701.4mV
152.1ps   641.7mV    295.4mV    835.8mV
197.7ps   776.9mV    485.3mV    872.8mV
255.3ps   821.9mV    662.3mV    884.2mV
331.6ps   831.8mV    767.8mV    886.4mV
625.1ps   833.5mV    794.6mV    886.9mV
[Falling Waveform]
R_fixture = 50
V_fixture = 1.5001
V_fixture_min = 1.425
V_fixture_max = 1.575
|   time   V(typ)   V(min)   V(max)
0s        1.499V     1.424V     1.575V
26.79ps   1.464V     1.424V     1.477V
52.47ps   1.391V     1.409V     1.311V
112.2ps   1.059V     1.314V     859.2mV
156.4ps   831mV      1.17V      731.9mV
194.4ps   726.9mV    1.012V     701.6mV
250.5ps   680.5mV    813mV      690.3mV
330.6ps   669.9mV    676.5mV    688mV
390.4ps   668.9mV    647.5mV    687.8mV
617.4ps   668.6mV    638.2mV    687.6mV
[Falling Waveform]
R_fixture = 50
V_fixture = 0
V_fixture_min = 0
V_fixture_max = 0
|   time   V(typ)   V(min)   V(max)
0s        832.6mV    794mV      886mV
23.09ps   803.1mV    793.8mV    818.6mV
46.09ps   727.1mV    776.6mV    681.4mV
108.3ps   370.3mV    621mV      194.7mV
151ps     162.9mV    456.7mV    51.46mV
182.2ps   71.61mV    333mV      19.88mV
226.3ps   20.19mV    186.1mV    5.455mV
313ps     2.03mV     44.3mV     0V
387.4ps   0V         6.739mV    0V
625.1ps   0V         0V         0V
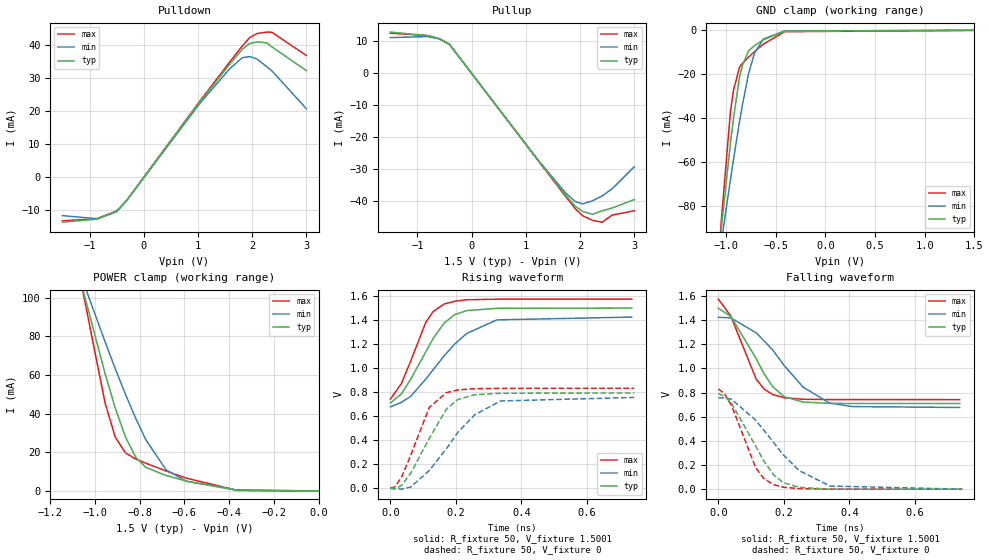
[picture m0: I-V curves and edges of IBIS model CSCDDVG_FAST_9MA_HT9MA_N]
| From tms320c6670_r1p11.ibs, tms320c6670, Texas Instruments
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|   Model Cell CSCDDVG_FAST_9MA_HT9MA_N
|FAST_9MA
[Model]   CSCDDVG_FAST_9MA_HT9MA_N
Model_type   I/O
Polarity   Non-Inverting
Enable   Active-Low
Cref =  4.0000pF
Rref =  100.0000M
Vref =  0V
Vmeas =  0.75
C_comp   1.5249p   1.4275p   1.6205p
|[mode_tieoffpin] SR0=1  SR1=0 I0=1 I1=0 I2=1
[Model Spec]
Vinl   0.6125   0.6125   0.6125
Vinh   0.9625   0.9625   0.9625
D_overshoot_high 1.95 1.95 1.95
D_overshoot_low -0.3 -0.3 -0.3
D_overshoot_time 1E-9 1E-9 1E-9
S_overshoot_high 1.575 1.575 1.575
S_overshoot_low 0 0 0
[Receiver Thresholds]
Vcross_low = 0.5625V
Vcross_high = 0.9375V
Vdiff_ac = +350mV
Vdiff_dc = +200mV
Tdiffslew_ac = 350ps
[Add Submodel]|Submodel_name Mode
DIFF_HT_TH_9MA Non-Driving
[Temperature Range]   25   105   -40
[Voltage Range]   1.5   1.425   1.575
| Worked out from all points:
|   slope of the pulldown table from 0 to 0.225 V, typ, clamps not added: 44.4 ohm
|   slope of the pullup table from 0 to 0.225 V, typ, clamps not added: 44.4 ohm
|   GND clamp passes 1 mA (typ) near -0.47 V on its own axis
|   POWER clamp passes 1 mA (typ) near -0.42 V on its own axis
|   rising waveform, R_fixture 50, V_fixture 1.5001: 20-80 % time 101ps typ, 145ps min, 74.9ps max; typ from 0.71 V to 1.5 V
|   rising waveform, R_fixture 50, V_fixture 0: 20-80 % time 95.7ps typ, 135ps min, 71.1ps max; typ from 0 V to 0.793 V
|   falling waveform, R_fixture 50, V_fixture 1.5001: 20-80 % time 99.3ps typ, 144ps min, 73.9ps max; typ from 1.5 V to 0.709 V
|   falling waveform, R_fixture 50, V_fixture 0: 20-80 % time 99ps typ, 145ps min, 72ps max; typ from 0.792 V to 0 V
[POWER_clamp]
|   voltage   I(typ)   I(min)   I(max)
-1.5V     321.7mA    260.6mA    415.9mA
-1.076V   114.2mA    115.8mA    116.9mA
-1.061V   107.2mA    110.9mA    107.1mA
-954.6mV  60.59mA    77.06mA    45.35mA
-909.2mV  42.85mA    63.21mA    27.81mA
-863.7mV  27.9mA     49.99mA    19.69mA
-818.2mV  17.49mA    37.63mA    16.52mA
-772.8mV  12.19mA    26.53mA    14.33mA
-681.9mV  7.985mA    10.89mA    10.33mA
-590.9mV  5.094mA    4.955mA    6.6mA
-363.7mV  298.5uA    465.2uA    297.6uA
0V        1.518nA    24.08nA    367.8pA
[Pulldown]
|   voltage   I(typ)   I(min)   I(max)
-1.5V     -13.72mA   -11.73mA   -13.31mA
-863.7mV  -12.8mA    -12.65mA   -12.66mA
-500mV    -10.46mA   -10.55mA   -10.29mA
-318.2mV  -7.172mA   -7.186mA   -7.182mA
1.046V    23.05mA    22.61mA    23.31mA
1.591V    34.39mA    33mA       35.06mA
1.818V    38.82mA    36.24mA    39.81mA
1.955V    40.55mA    36.61mA    42.37mA
2.091V    41.08mA    35.83mA    43.61mA
2.273V    40.74mA    33.5mA     44.04mA
2.364V    39.55mA    32.26mA    43.99mA
3V        32.34mA    20.77mA    36.92mA
[Pullup]
|   voltage   I(typ)   I(min)   I(max)
-1.5V     12.66mA    10.94mA    12.31mA
-818.2mV  11.55mA    11.26mA    11.58mA
-590.9mV  10.61mA    10.52mA    10.54mA
-409.1mV  8.836mA    8.777mA    8.84mA
1.227V    -27.25mA   -27.19mA   -27.38mA
1.727V    -37.96mA   -37.32mA   -38.38mA
1.909V    -41.55mA   -40.1mA    -42.29mA
2.046V    -43.18mA   -40.84mA   -44.51mA
2.227V    -44.08mA   -39.9mA    -45.94mA
2.409V    -42.96mA   -38.35mA   -46.53mA
2.591V    -42.11mA   -36.14mA   -44.31mA
3V        -39.5mA    -29.28mA   -42.98mA
[GND_clamp]
|   voltage   I(typ)   I(min)   I(max)
-1.5V     -310.1mA   -250.5mA   -402.5mA
-1.076V   -103.6mA   -106.2mA   -105.2mA
-1.046V   -89.81mA   -96.36mA   -86.02mA
-954.6mV  -51.22mA   -67.87mA   -36.88mA
-924.3mV  -40.08mA   -58.86mA   -27.29mA
-863.7mV  -21.24mA   -41.56mA   -16.73mA
-833.4mV  -15.8mA    -33.75mA   -15.03mA
-772.8mV  -9.345mA   -19.75mA   -12.19mA
-712.2mV  -6.928mA   -10.35mA   -9.704mA
-621.3mV  -4.261mA   -3.896mA   -6.225mA
-409.1mV  -337.1uA   -289.1uA   -618.9uA
1.5V      1.518nA    257.2nA    299pA
[Ramp]
| variable   typ   min   max
dV/dt_f   0.632752/0.14700507n   0.598864/0.21860086n   0.666584/0.11454368n
dV/dt_r 0.63894896/0.14120975n 0.61111208/0.20900305n 0.66816984/0.10960734n
R_load = 50
[Rising Waveform]
R_fixture = 50
V_fixture = 1.5001
V_fixture_min = 1.425
V_fixture_max = 1.575
|   time   V(typ)   V(min)   V(max)
0s        709.9mV    677.4mV    742.6mV
33.32ps   784.9mV    714.7mV    870.8mV
61.63ps   905.8mV    764.2mV    1.056V
107.8ps   1.134V     907.4mV    1.38V
130.6ps   1.247V     986.7mV    1.471V
163.8ps   1.374V     1.101V     1.533V
196ps     1.445V     1.2V       1.557V
233.2ps   1.479V     1.289V     1.569V
325.6ps   1.498V     1.402V     1.574V
737.1ps   1.5V       1.425V     1.575V
[Rising Waveform]
R_fixture = 50
V_fixture = 0
V_fixture_min = 0
V_fixture_max = 0
|   time   V(typ)   V(min)   V(max)
0s        0V         0V         0V
14.24ps   -5.641mV   -1.838mV   12.44mV
34.98ps   26.64mV    -7.269mV   97.78mV
61.77ps   123.4mV    10.36mV    272.8mV
118.7ps   415.6mV    147.9mV    673mV
170.6ps   657.5mV    327.9mV    795.5mV
206.5ps   740.4mV    467mV      818.8mV
257.6ps   778.8mV    612mV      829mV
336.3ps   790.9mV    726.9mV    832.1mV
744.7ps   793mV      756.2mV    832.8mV
[Falling Waveform]
R_fixture = 50
V_fixture = 1.5001
V_fixture_min = 1.425
V_fixture_max = 1.575
|   time   V(typ)   V(min)   V(max)
0s        1.499V     1.424V     1.575V
38.29ps   1.431V     1.419V     1.433V
115.2ps   1.083V     1.296V     914.4mV
139.3ps   958.4mV    1.23V      830.2mV
165.9ps   849.6mV    1.154V     783.8mV
201.5ps   765.5mV    1.023V     757.6mV
258.6ps   722mV      845.9mV    744.9mV
339ps     710.9mV    714.3mV    742.4mV
408.7ps   709.6mV    684.2mV    742.1mV
737.1ps   709.3mV    676.9mV    741.9mV
[Falling Waveform]
R_fixture = 50
V_fixture = 0
V_fixture_min = 0
V_fixture_max = 0
|   time   V(typ)   V(min)   V(max)
0s        792.3mV    755.5mV    831.9mV
19.58ps   768.6mV    756mV      789.2mV
40.67ps   709.7mV    744.7mV    690.6mV
114ps     357.4mV    571.7mV    179mV
139.3ps   231.8mV    487.4mV    86.92mV
169.1ps   118.3mV    387.1mV    36.92mV
197.8ps   55.44mV    286.1mV    16.35mV
247.4ps   14.86mV    152.6mV    4.302mV
340.9ps   0V         26.03mV    0V
744.7ps   0V         0V         0V
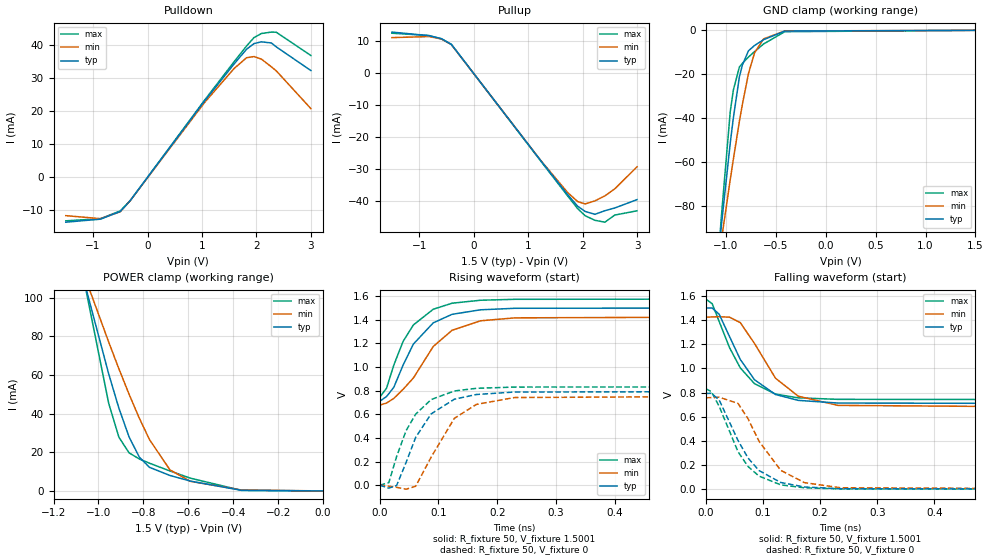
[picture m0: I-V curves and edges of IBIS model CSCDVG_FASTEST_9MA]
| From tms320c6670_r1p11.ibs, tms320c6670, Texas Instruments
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|   Model Cell CSCDVG_FASTEST_9MA
|FASTEST_9MA
[Model]   CSCDVG_FASTEST_9MA
Model_type   3-state
Polarity   Non-Inverting
Enable   Active-Low
Cref =  4.0000pF
Rref =  100.0000M
Vref =  0V
Vmeas =  0.75
C_comp   1.5249p   1.4275p   1.6205p
[Temperature Range]   25   105   -40
[Voltage Range]   1.5   1.425   1.575
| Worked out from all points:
|   slope of the pulldown table from 0 to 0.225 V, typ, clamps not added: 44.4 ohm
|   slope of the pullup table from 0 to 0.225 V, typ, clamps not added: 44.4 ohm
|   GND clamp passes 1 mA (typ) near -0.47 V on its own axis
|   POWER clamp passes 1 mA (typ) near -0.42 V on its own axis
|   rising waveform, R_fixture 50, V_fixture 1.5001: 20-80 % time 54.4ps typ, 69.4ps min, 49.9ps max; typ from 0.71 V to 1.5 V
|   rising waveform, R_fixture 50, V_fixture 0: 20-80 % time 51.8ps typ, 55.6ps min, 48.2ps max; typ from 0 V to 0.793 V
|   falling waveform, R_fixture 50, V_fixture 1.5001: 20-80 % time 59ps typ, 65.3ps min, 54.9ps max; typ from 1.5 V to 0.709 V
|   falling waveform, R_fixture 50, V_fixture 0: 20-80 % time 57.2ps typ, 60.9ps min, 52.8ps max; typ from 0.793 V to 0 V
[POWER_clamp]
|   voltage   I(typ)   I(min)   I(max)
-1.5V     321.7mA    260.6mA    415.9mA
-1.076V   114.2mA    115.8mA    116.9mA
-1.061V   107.2mA    110.9mA    107.1mA
-954.6mV  60.59mA    77.06mA    45.35mA
-909.2mV  42.85mA    63.21mA    27.81mA
-863.7mV  27.9mA     49.99mA    19.69mA
-818.2mV  17.49mA    37.63mA    16.52mA
-772.8mV  12.19mA    26.53mA    14.33mA
-681.9mV  7.985mA    10.89mA    10.33mA
-590.9mV  5.094mA    4.955mA    6.6mA
-363.7mV  298.5uA    465.2uA    297.6uA
0V        1.518nA    24.08nA    367.8pA
[Pulldown]
|   voltage   I(typ)   I(min)   I(max)
-1.5V     -13.72mA   -11.73mA   -13.31mA
-863.7mV  -12.8mA    -12.65mA   -12.66mA
-500mV    -10.46mA   -10.55mA   -10.29mA
-318.2mV  -7.172mA   -7.186mA   -7.182mA
1.046V    23.05mA    22.61mA    23.31mA
1.591V    34.39mA    33mA       35.06mA
1.818V    38.82mA    36.24mA    39.81mA
1.955V    40.55mA    36.61mA    42.37mA
2.091V    41.08mA    35.83mA    43.61mA
2.273V    40.74mA    33.5mA     44.04mA
2.364V    39.55mA    32.26mA    43.99mA
3V        32.34mA    20.77mA    36.92mA
[Pullup]
|   voltage   I(typ)   I(min)   I(max)
-1.5V     12.66mA    10.94mA    12.31mA
-818.2mV  11.55mA    11.26mA    11.58mA
-590.9mV  10.61mA    10.52mA    10.54mA
-409.1mV  8.836mA    8.777mA    8.84mA
1.227V    -27.25mA   -27.19mA   -27.38mA
1.727V    -37.96mA   -37.32mA   -38.38mA
1.909V    -41.55mA   -40.1mA    -42.29mA
2.046V    -43.18mA   -40.84mA   -44.51mA
2.227V    -44.08mA   -39.9mA    -45.94mA
2.409V    -42.96mA   -38.35mA   -46.53mA
2.591V    -42.11mA   -36.14mA   -44.31mA
3V        -39.5mA    -29.28mA   -42.98mA
[GND_clamp]
|   voltage   I(typ)   I(min)   I(max)
-1.5V     -310.1mA   -250.5mA   -402.5mA
-1.076V   -103.6mA   -106.2mA   -105.2mA
-1.046V   -89.81mA   -96.36mA   -86.02mA
-954.6mV  -51.22mA   -67.87mA   -36.88mA
-924.3mV  -40.08mA   -58.86mA   -27.29mA
-863.7mV  -21.24mA   -41.56mA   -16.73mA
-833.4mV  -15.8mA    -33.75mA   -15.03mA
-772.8mV  -9.345mA   -19.75mA   -12.19mA
-712.2mV  -6.928mA   -10.35mA   -9.704mA
-621.3mV  -4.261mA   -3.896mA   -6.225mA
-409.1mV  -337.1uA   -289.1uA   -618.9uA
1.5V      1.518nA    257.2nA    299pA
[Ramp]
| variable   typ   min   max
dV/dt_f   0.636912/93.554374p   0.602712/0.10536803n   0.668424/85.90732p
dV/dt_r   0.656732/84.321741p  0.6328336/91.397271p  0.6817744/76.969402p
R_load = 50
[Rising Waveform]
R_fixture = 50
V_fixture = 1.5001
V_fixture_min = 1.425
V_fixture_max = 1.575
|   time   V(typ)   V(min)   V(max)
0s        709.9mV    677.4mV    742.6mV
11.71ps   749.9mV    695.1mV    820.6mV
24.11ps   828.5mV    734.5mV    1.017V
39.92ps   1.017V     811.4mV    1.217V
57.34ps   1.194V     907mV      1.356V
91.21ps   1.374V     1.174V     1.489V
123.2ps   1.446V     1.311V     1.54V
171.4ps   1.484V     1.391V     1.565V
230.2ps   1.497V     1.416V     1.573V
746.7ps   1.5V       1.425V     1.575V
[Rising Waveform]
R_fixture = 50
V_fixture = 0
V_fixture_min = 0
V_fixture_max = 0
|   time   V(typ)   V(min)   V(max)
0s        0V         0V         0V
15.58ps   -24.78mV   -8.501mV   21.04mV
28.8ps    -3.283mV   -18.21mV   241.7mV
45.01ps   193.3mV    -33.66mV   462.3mV
61.2ps    404.1mV    -9.334mV   600.6mV
87.57ps   603.5mV    237.6mV    724.6mV
127ps     727.5mV    565.5mV    797.1mV
164.4ps   767.4mV    683.5mV    819.8mV
229.3ps   788.3mV    741.7mV    830.3mV
818.3ps   793mV      756.2mV    832.8mV
[Falling Waveform]
R_fixture = 50
V_fixture = 1.5001
V_fixture_min = 1.425
V_fixture_max = 1.575
|   time   V(typ)   V(min)   V(max)
0s        1.501V     1.425V     1.575V
11.11ps   1.501V     1.427V     1.537V
23.47ps   1.449V     1.429V     1.389V
41.58ps   1.264V     1.425V     1.172V
60.34ps   1.075V     1.38V      1.005V
85.26ps   906.5mV    1.207V     873.8mV
122ps     784.2mV    919.2mV    787.8mV
161.8ps   735.6mV    770.2mV    756.5mV
231.2ps   713.5mV    694.1mV    744.2mV
746.7ps   709.3mV    676.9mV    741.9mV
[Falling Waveform]
R_fixture = 50
V_fixture = 0
V_fixture_min = 0
V_fixture_max = 0
|   time   V(typ)   V(min)   V(max)
0s        793mV      756.9mV    832.6mV
9.814ps   794.3mV    758.8mV    807.5mV
23.35ps   739.9mV    761.8mV    687.3mV
56.45ps   403.1mV    710.3mV    309.4mV
74.02ps   257.4mV    582.6mV    187.6mV
93.11ps   154.5mV    397.2mV    108.3mV
131.1ps   55.41mV    156.2mV    35.59mV
172.8ps   17.89mV    53.75mV    10.93mV
235.9ps   3.719mV    11.67mV    2.174mV
818.3ps   0V         0V         0V
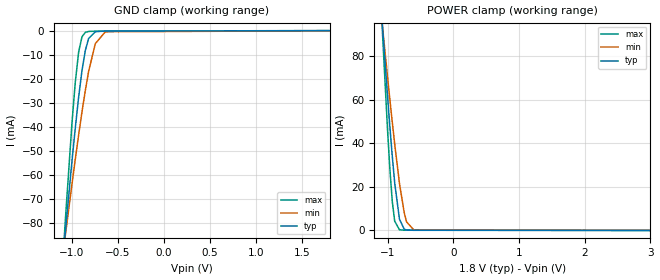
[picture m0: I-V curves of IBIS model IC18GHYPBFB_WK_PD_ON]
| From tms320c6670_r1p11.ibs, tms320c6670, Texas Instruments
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|   Model Cell IC18GHYPBFB_WK_PD_ON
|IC18GHYPBFB_WK_PD_ON
[Model]   IC18GHYPBFB_WK_PD_ON
Model_type   Input
Polarity   Non-Inverting
Vinl =  0.63
Vinh =  1.17
C_comp   0.740644p   0.691188p   0.796707p
[Model Spec]
Vinl   0.63   0.5985   0.6615
Vinh   1.17   1.1115   1.2285
D_overshoot_high 2.34 2.34 2.34
D_overshoot_low -0.3 -0.3 -0.3
D_overshoot_time 1.00E-09 1.00E-09 1.00E-09
S_overshoot_high 1.98 1.98 1.98
S_overshoot_low 0 0 0
[Temperature Range]   25   105   -40
[Voltage Range]   1.8   1.71   1.89
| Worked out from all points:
|   GND clamp passes 1 mA (typ) near -0.78 V on its own axis
|   POWER clamp passes 1 mA (typ) near -0.76 V on its own axis
[POWER_clamp]
|   voltage   I(typ)   I(min)   I(max)
-1.8V     427.4mA    328.2mA    578.5mA
-1.109V   107.9mA    103.8mA    111.2mA
-1.073V   92.15mA    92.58mA    88.63mA
-1V       61.78mA    70.65mA    46.39mA
-963.6mV  47.44mA    60.01mA    28mA
-927.3mV  33.98mA    49.66mA    13.25mA
-890.9mV  21.89mA    39.71mA    4.304mA
-818.2mV  5.182mA    21.65mA    310.5uA
-745.5mV  565.3uA    8.051mA    144.4uA
-709.1mV  212.7uA    3.909mA    137.9uA
-600mV    91.1uA     256.6uA    133.3uA
3.6V      0A         0A         0A
[GND_clamp]
|   voltage   I(typ)   I(min)   I(max)
-1.8V     -418.5mA   -320.6mA   -568mA
-1.109V   -99.81mA   -96.73mA   -101.8mA
-1.073V   -84.25mA   -85.62mA   -79.6mA
-1V       -54.4mA    -63.96mA   -38.55mA
-963.6mV  -40.48mA   -53.5mA    -21.44mA
-927.3mV  -27.66mA   -43.4mA    -8.854mA
-890.9mV  -16.56mA   -33.77mA   -2.484mA
-854.5mV  -8.139mA   -24.82mA   -617.1uA
-818.2mV  -3.112mA   -16.81mA   -220.3uA
-745.5mV  -335.4uA   -5.278mA   -124.3uA
-636.4mV  -79.47uA   -364.9uA   -100.8uA
1.8V      87.08uA    51.59uA    129.7uA
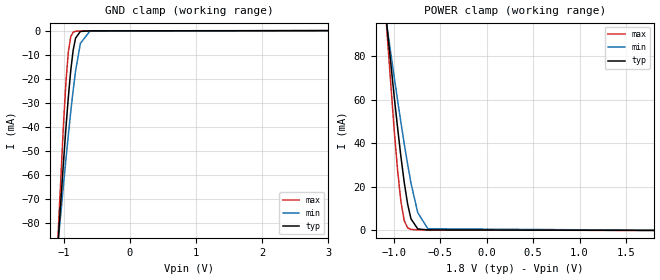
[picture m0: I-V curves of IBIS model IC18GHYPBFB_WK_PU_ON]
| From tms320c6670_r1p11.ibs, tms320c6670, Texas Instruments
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|   Model Cell IC18GHYPBFB_WK_PU_ON
|IC18GHYPBFB_WK_PU_ON
[Model]   IC18GHYPBFB_WK_PU_ON
Model_type   Input
Polarity   Non-Inverting
Vinl =  0.63
Vinh =  1.17
C_comp   0.740644p   0.691188p   0.796707p
[Model Spec]
Vinl   0.63   0.5985   0.6615
Vinh   1.17   1.1115   1.2285
D_overshoot_high 2.34 2.34 2.34
D_overshoot_low -0.3 -0.3 -0.3
D_overshoot_time 1.00E-09 1.00E-09 1.00E-09
S_overshoot_high 1.98 1.98 1.98
S_overshoot_low 0 0 0
[Temperature Range]   25   105   -40
[Voltage Range]   1.8   1.71   1.89
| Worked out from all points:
|   GND clamp passes 1 mA (typ) near -0.78 V on its own axis
|   POWER clamp passes 1 mA (typ) near -0.76 V on its own axis
[POWER_clamp]
|   voltage   I(typ)   I(min)   I(max)
-1.8V     427.4mA    328.2mA    578.5mA
-1.109V   107.9mA    103.8mA    111.2mA
-1.073V   92.18mA    92.58mA    88.67mA
-1V       61.81mA    70.66mA    46.43mA
-963.6mV  47.47mA    60.02mA    28.04mA
-927.3mV  34.01mA    49.68mA    13.29mA
-890.9mV  21.92mA    39.73mA    4.332mA
-854.5mV  12.01mA    30.32mA    1.089mA
-818.2mV  5.203mA    21.67mA    330.4uA
-745.5mV  580.1uA    8.069mA    154.9uA
-636.4mV  99.07uA    652.7uA    127.1uA
1.8V      -99.58uA   -64.17uA   -149.9uA
[GND_clamp]
|   voltage   I(typ)   I(min)   I(max)
-1.8V     -418.5mA   -320.6mA   -568mA
-1.109V   -99.83mA   -96.73mA   -101.9mA
-1.073V   -84.27mA   -85.63mA   -79.64mA
-1V       -54.42mA   -63.96mA   -38.6mA
-963.6mV  -40.5mA    -53.51mA   -21.49mA
-927.3mV  -27.68mA   -43.41mA   -8.902mA
-890.9mV  -16.58mA   -33.78mA   -2.533mA
-854.5mV  -8.164mA   -24.83mA   -668.7uA
-818.2mV  -3.139mA   -16.82mA   -273.6uA
-745.5mV  -365uA     -5.295mA   -181.2uA
-600mV    -109.2uA   -177.3uA   -162.2uA
3.6V      0A         0A         0A
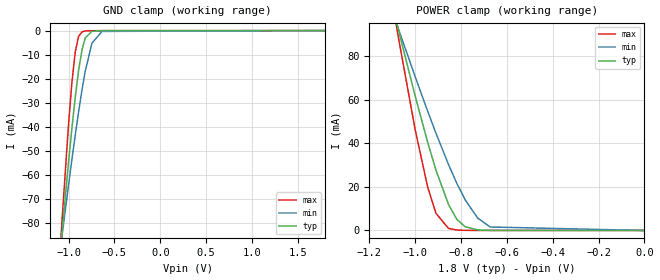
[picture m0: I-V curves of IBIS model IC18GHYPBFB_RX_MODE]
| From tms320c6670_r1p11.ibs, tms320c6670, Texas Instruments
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|   Model Cell IC18GHYPBFB_RX_MODE
|IC18GHYPBFB_RX_MODE
[Model]   IC18GHYPBFB_RX_MODE
Model_type   Input
Polarity   Non-Inverting
Vinl =  0.63
Vinh =  1.17
C_comp   0.740644p   0.691188p   0.796707p
[Model Spec]
Vinl   0.63   0.5985   0.6615
Vinh   1.17   1.1115   1.2285
D_overshoot_high 2.34 2.34 2.34
D_overshoot_low -0.3 -0.3 -0.3
D_overshoot_time 1.00E-09 1.00E-09 1.00E-09
S_overshoot_high 1.98 1.98 1.98
S_overshoot_low 0 0 0
[Temperature Range]   25   105   -40
[Voltage Range]   1.8   1.71   1.89
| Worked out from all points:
|   GND clamp passes 1 mA (typ) near -0.78 V on its own axis
|   POWER clamp passes 1 mA (typ) near -0.77 V on its own axis
[POWER_clamp]
|   voltage   I(typ)   I(min)   I(max)
-1.8V     427.4mA    328.2mA    578.5mA
-1.091V   99.96mA    98.15mA    99.75mA
-1.073V   92.13mA    92.57mA    88.56mA
-1V       61.75mA    70.64mA    46.3mA
-945.5mV  40.53mA    54.78mA    19.94mA
-909.1mV  27.67mA    44.62mA    7.835mA
-854.5mV  11.92mA    30.29mA    955.8uA
-818.2mV  5.112mA    21.63mA    199uA
-781.8mV  1.703mA    14.06mA    57.53uA
-727.3mV  255.8uA    5.698mA    23.9uA
-672.7mV  41.28uA    1.606mA    15.74uA
0V        9.084nA    6.33nA     15.65nA
[GND_clamp]
|   voltage   I(typ)   I(min)   I(max)
-1.8V     -418.5mA   -320.6mA   -568mA
-1.109V   -99.79mA   -96.72mA   -101.8mA
-1.073V   -84.23mA   -85.61mA   -79.54mA
-1V       -54.36mA   -63.95mA   -38.49mA
-963.6mV  -40.44mA   -53.49mA   -21.38mA
-927.3mV  -27.62mA   -43.39mA   -8.794mA
-890.9mV  -16.51mA   -33.76mA   -2.422mA
-854.5mV  -8.093mA   -24.8mA    -555.3uA
-818.2mV  -3.065mA   -16.79mA   -158.3uA
-745.5mV  -287.2uA   -5.251mA   -61.89uA
-636.4mV  -31.02uA   -333.8uA   -37.76uA
1.8V      9.084nA    6.401nA    15.63nA
